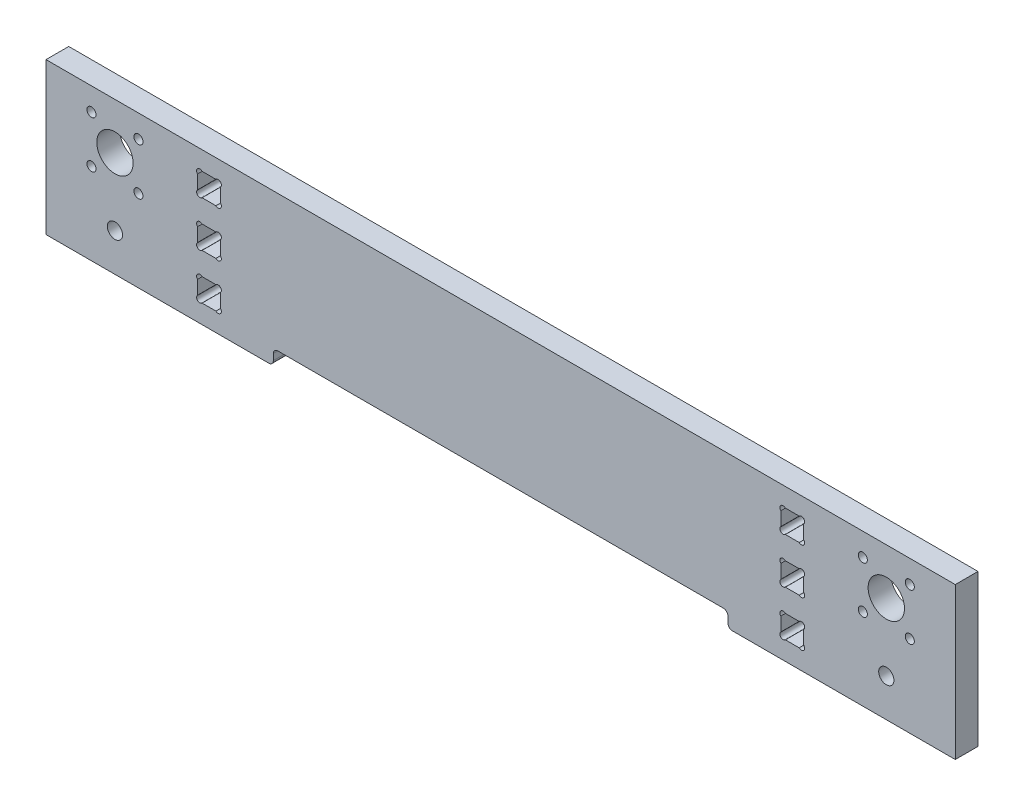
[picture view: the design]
ISO-10303-21;
HEADER;
FILE_DESCRIPTION(('STEP AP214'),'2;1');
FILE_NAME('part.step','',(''),(''),'','','');
FILE_SCHEMA(('AUTOMOTIVE_DESIGN { 1 0 10303 214 1 1 1 1 }'));
ENDSEC;
DATA;
#1=APPLICATION_CONTEXT('core data for automotive mechanical design processes');
#2=APPLICATION_PROTOCOL_DEFINITION('international standard','automotive_design',2000,#1);
#3=PRODUCT_CONTEXT('',#1,'mechanical');
#4=PRODUCT('Part','Part','',(#3));
#5=PRODUCT_RELATED_PRODUCT_CATEGORY('part','',(#4));
#6=PRODUCT_DEFINITION_FORMATION('','',#4);
#7=PRODUCT_DEFINITION_CONTEXT('part definition',#1,'design');
#8=PRODUCT_DEFINITION('design','',#6,#7);
#9=PRODUCT_DEFINITION_SHAPE('','',#8);
#10=(LENGTH_UNIT() NAMED_UNIT(*) SI_UNIT(.MILLI.,.METRE.));
#11=(NAMED_UNIT(*) PLANE_ANGLE_UNIT() SI_UNIT($,.RADIAN.));
#12=(NAMED_UNIT(*) SI_UNIT($,.STERADIAN.) SOLID_ANGLE_UNIT());
#13=UNCERTAINTY_MEASURE_WITH_UNIT(LENGTH_MEASURE(1.E-05),#10,'distance_accuracy_value','');
#14=(GEOMETRIC_REPRESENTATION_CONTEXT(3) GLOBAL_UNCERTAINTY_ASSIGNED_CONTEXT((#13)) GLOBAL_UNIT_ASSIGNED_CONTEXT((#10,
#11,#12)) REPRESENTATION_CONTEXT('',''));
#15=CARTESIAN_POINT('',(0.,0.,0.));
#16=DIRECTION('',(0.,0.,1.));
#17=DIRECTION('',(1.,0.,0.));
#18=AXIS2_PLACEMENT_3D('',#15,#16,#17);
#19=CARTESIAN_POINT('',(0.,0.,15.));
#20=DIRECTION('',(0.,0.,-1.));
#21=DIRECTION('',(-1.,0.,0.));
#22=AXIS2_PLACEMENT_3D('',#19,#20,#21);
#23=PLANE('',#22);
#24=CARTESIAN_POINT('',(45.5,25.,15.));
#25=DIRECTION('',(0.,0.,1.));
#26=DIRECTION('',(1.,0.,0.));
#27=AXIS2_PLACEMENT_3D('',#24,#25,#26);
#28=CIRCLE('',#27,5.025);
#29=CARTESIAN_POINT('',(50.5249999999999,25.,15.));
#30=VERTEX_POINT('',#29);
#31=EDGE_CURVE('E1678',#30,#30,#28,.T.);
#32=ORIENTED_EDGE('',*,*,#31,.F.);
#33=EDGE_LOOP('',(#32));
#34=FACE_BOUND('',#33,.T.);
#35=CARTESIAN_POINT('',(554.5,25.,15.));
#36=DIRECTION('',(0.,0.,1.));
#37=DIRECTION('',(1.,0.,0.));
#38=AXIS2_PLACEMENT_3D('',#35,#36,#37);
#39=CIRCLE('',#38,5.025);
#40=CARTESIAN_POINT('',(559.525,25.,15.));
#41=VERTEX_POINT('',#40);
#42=EDGE_CURVE('E1677',#41,#41,#39,.T.);
#43=ORIENTED_EDGE('',*,*,#42,.F.);
#44=EDGE_LOOP('',(#43));
#45=FACE_BOUND('',#44,.T.);
#46=CARTESIAN_POINT('',(539.,85.,15.));
#47=DIRECTION('',(0.,0.,1.));
#48=DIRECTION('',(1.,0.,0.));
#49=AXIS2_PLACEMENT_3D('',#46,#47,#48);
#50=CIRCLE('',#49,3.00000000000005);
#51=CARTESIAN_POINT('',(542.,85.,15.));
#52=VERTEX_POINT('',#51);
#53=EDGE_CURVE('E1689',#52,#52,#50,.T.);
#54=ORIENTED_EDGE('',*,*,#53,.F.);
#55=EDGE_LOOP('',(#54));
#56=FACE_BOUND('',#55,.T.);
#57=CARTESIAN_POINT('',(570.,85.,15.));
#58=DIRECTION('',(0.,0.,1.));
#59=DIRECTION('',(1.,0.,0.));
#60=AXIS2_PLACEMENT_3D('',#57,#58,#59);
#61=CIRCLE('',#60,3.00000000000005);
#62=CARTESIAN_POINT('',(573.,85.,15.));
#63=VERTEX_POINT('',#62);
#64=EDGE_CURVE('E1695',#63,#63,#61,.T.);
#65=ORIENTED_EDGE('',*,*,#64,.F.);
#66=EDGE_LOOP('',(#65));
#67=FACE_BOUND('',#66,.T.);
#68=CARTESIAN_POINT('',(570.,54.,15.));
#69=DIRECTION('',(0.,0.,1.));
#70=DIRECTION('',(1.,0.,0.));
#71=AXIS2_PLACEMENT_3D('',#68,#69,#70);
#72=CIRCLE('',#71,3.00000000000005);
#73=CARTESIAN_POINT('',(573.,54.,15.));
#74=VERTEX_POINT('',#73);
#75=EDGE_CURVE('E1703',#74,#74,#72,.T.);
#76=ORIENTED_EDGE('',*,*,#75,.F.);
#77=EDGE_LOOP('',(#76));
#78=FACE_BOUND('',#77,.T.);
#79=CARTESIAN_POINT('',(554.5,69.5,15.));
#80=DIRECTION('',(0.,0.,1.));
#81=DIRECTION('',(1.,0.,0.));
#82=AXIS2_PLACEMENT_3D('',#79,#80,#81);
#83=CIRCLE('',#82,12.);
#84=CARTESIAN_POINT('',(566.5,69.5,15.));
#85=VERTEX_POINT('',#84);
#86=EDGE_CURVE('E1711',#85,#85,#83,.T.);
#87=ORIENTED_EDGE('',*,*,#86,.F.);
#88=EDGE_LOOP('',(#87));
#89=FACE_BOUND('',#88,.T.);
#90=CARTESIAN_POINT('',(539.,54.,15.));
#91=DIRECTION('',(0.,0.,1.));
#92=DIRECTION('',(1.,0.,0.));
#93=AXIS2_PLACEMENT_3D('',#90,#91,#92);
#94=CIRCLE('',#93,3.00000000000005);
#95=CARTESIAN_POINT('',(542.,54.,15.));
#96=VERTEX_POINT('',#95);
#97=EDGE_CURVE('E423',#96,#96,#94,.T.);
#98=ORIENTED_EDGE('',*,*,#97,.F.);
#99=EDGE_LOOP('',(#98));
#100=FACE_BOUND('',#99,.T.);
#101=DIRECTION('',(-1.,0.,0.));
#102=VECTOR('',#101,1.);
#103=CARTESIAN_POINT('',(497.,27.4500000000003,15.));
#104=LINE('',#103,#102);
#105=CARTESIAN_POINT('',(497.,27.4500000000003,15.));
#106=VERTEX_POINT('',#105);
#107=CARTESIAN_POINT('',(487.9,27.4500000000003,15.));
#108=VERTEX_POINT('',#107);
#109=EDGE_CURVE('E436',#106,#108,#104,.T.);
#110=ORIENTED_EDGE('',*,*,#109,.F.);
#111=CARTESIAN_POINT('',(498.5,25.9500000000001,15.));
#112=DIRECTION('',(0.,0.,1.));
#113=DIRECTION('',(1.,0.,0.));
#114=AXIS2_PLACEMENT_3D('',#111,#112,#113);
#115=CIRCLE('',#114,2.12132034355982);
#116=CARTESIAN_POINT('',(500.,24.4499999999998,15.));
#117=VERTEX_POINT('',#116);
#118=EDGE_CURVE('E415',#117,#106,#115,.T.);
#119=ORIENTED_EDGE('',*,*,#118,.F.);
#120=DIRECTION('',(0.,1.,0.));
#121=VECTOR('',#120,1.);
#122=CARTESIAN_POINT('',(500.,15.3499999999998,15.));
#123=LINE('',#122,#121);
#124=CARTESIAN_POINT('',(500.,15.3499999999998,15.));
#125=VERTEX_POINT('',#124);
#126=EDGE_CURVE('E426',#125,#117,#123,.T.);
#127=ORIENTED_EDGE('',*,*,#126,.F.);
#128=CARTESIAN_POINT('',(498.5,13.8499999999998,15.));
#129=DIRECTION('',(0.,0.,1.));
#130=DIRECTION('',(1.,0.,0.));
#131=AXIS2_PLACEMENT_3D('',#128,#129,#130);
#132=CIRCLE('',#131,2.12132034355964);
#133=CARTESIAN_POINT('',(497.,12.3499999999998,15.));
#134=VERTEX_POINT('',#133);
#135=EDGE_CURVE('E431',#134,#125,#132,.T.);
#136=ORIENTED_EDGE('',*,*,#135,.F.);
#137=DIRECTION('',(1.,0.,0.));
#138=VECTOR('',#137,1.);
#139=CARTESIAN_POINT('',(487.9,12.3499999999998,15.));
#140=LINE('',#139,#138);
#141=CARTESIAN_POINT('',(487.9,12.3499999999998,15.));
#142=VERTEX_POINT('',#141);
#143=EDGE_CURVE('E1736',#142,#134,#140,.T.);
#144=ORIENTED_EDGE('',*,*,#143,.F.);
#145=CARTESIAN_POINT('',(486.4,13.8499999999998,15.));
#146=DIRECTION('',(0.,0.,1.));
#147=DIRECTION('',(1.,0.,0.));
#148=AXIS2_PLACEMENT_3D('',#145,#146,#147);
#149=CIRCLE('',#148,2.12132034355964);
#150=CARTESIAN_POINT('',(484.9,15.3499999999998,15.));
#151=VERTEX_POINT('',#150);
#152=EDGE_CURVE('E1739',#151,#142,#149,.T.);
#153=ORIENTED_EDGE('',*,*,#152,.F.);
#154=DIRECTION('',(0.,-1.,0.));
#155=VECTOR('',#154,1.);
#156=CARTESIAN_POINT('',(484.9,24.4499999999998,15.));
#157=LINE('',#156,#155);
#158=CARTESIAN_POINT('',(484.9,24.4499999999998,15.));
#159=VERTEX_POINT('',#158);
#160=EDGE_CURVE('E1742',#159,#151,#157,.T.);
#161=ORIENTED_EDGE('',*,*,#160,.F.);
#162=CARTESIAN_POINT('',(486.4,25.9500000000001,15.));
#163=DIRECTION('',(0.,0.,-1.));
#164=DIRECTION('',(-1.,0.,0.));
#165=AXIS2_PLACEMENT_3D('',#162,#163,#164);
#166=CIRCLE('',#165,2.12132034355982);
#167=EDGE_CURVE('E441',#159,#108,#166,.T.);
#168=ORIENTED_EDGE('',*,*,#167,.T.);
#169=EDGE_LOOP('',(#110,#119,#127,#136,#144,#153,#161,#168));
#170=FACE_BOUND('',#169,.T.);
#171=DIRECTION('',(0.,-1.,0.));
#172=VECTOR('',#171,1.);
#173=CARTESIAN_POINT('',(450.,0.,15.));
#174=LINE('',#173,#172);
#175=CARTESIAN_POINT('',(450.,6.99999999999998,15.));
#176=VERTEX_POINT('',#175);
#177=CARTESIAN_POINT('',(450.,2.99999999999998,15.));
#178=VERTEX_POINT('',#177);
#179=EDGE_CURVE('E819',#176,#178,#174,.T.);
#180=ORIENTED_EDGE('',*,*,#179,.T.);
#181=CARTESIAN_POINT('',(453.,2.99999999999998,15.));
#182=DIRECTION('',(0.,0.,-1.));
#183=DIRECTION('',(-1.,0.,0.));
#184=AXIS2_PLACEMENT_3D('',#181,#182,#183);
#185=CIRCLE('',#184,3.);
#186=CARTESIAN_POINT('',(453.,0.,15.));
#187=VERTEX_POINT('',#186);
#188=EDGE_CURVE('E873',#178,#187,#185,.F.);
#189=ORIENTED_EDGE('',*,*,#188,.T.);
#190=DIRECTION('',(1.,0.,0.));
#191=VECTOR('',#190,1.);
#192=CARTESIAN_POINT('',(600.,0.,15.));
#193=LINE('',#192,#191);
#194=CARTESIAN_POINT('',(600.,0.,15.));
#195=VERTEX_POINT('',#194);
#196=EDGE_CURVE('E822',#187,#195,#193,.T.);
#197=ORIENTED_EDGE('',*,*,#196,.T.);
#198=DIRECTION('',(0.,1.,0.));
#199=VECTOR('',#198,1.);
#200=CARTESIAN_POINT('',(600.,0.,15.));
#201=LINE('',#200,#199);
#202=CARTESIAN_POINT('',(600.,100.,15.));
#203=VERTEX_POINT('',#202);
#204=EDGE_CURVE('E824',#195,#203,#201,.T.);
#205=ORIENTED_EDGE('',*,*,#204,.T.);
#206=DIRECTION('',(-1.,0.,0.));
#207=VECTOR('',#206,1.);
#208=CARTESIAN_POINT('',(0.,100.,15.));
#209=LINE('',#208,#207);
#210=CARTESIAN_POINT('',(0.,100.,15.));
#211=VERTEX_POINT('',#210);
#212=EDGE_CURVE('E826',#203,#211,#209,.T.);
#213=ORIENTED_EDGE('',*,*,#212,.T.);
#214=DIRECTION('',(0.,-1.,0.));
#215=VECTOR('',#214,1.);
#216=CARTESIAN_POINT('',(0.,0.,15.));
#217=LINE('',#216,#215);
#218=CARTESIAN_POINT('',(0.,0.,15.));
#219=VERTEX_POINT('',#218);
#220=EDGE_CURVE('E828',#211,#219,#217,.T.);
#221=ORIENTED_EDGE('',*,*,#220,.T.);
#222=DIRECTION('',(1.,0.,0.));
#223=VECTOR('',#222,1.);
#224=CARTESIAN_POINT('',(150.,0.,15.));
#225=LINE('',#224,#223);
#226=CARTESIAN_POINT('',(147.,0.,15.));
#227=VERTEX_POINT('',#226);
#228=EDGE_CURVE('E811',#219,#227,#225,.T.);
#229=ORIENTED_EDGE('',*,*,#228,.T.);
#230=CARTESIAN_POINT('',(147.,3.00000000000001,15.));
#231=DIRECTION('',(0.,0.,-1.));
#232=DIRECTION('',(-1.,0.,0.));
#233=AXIS2_PLACEMENT_3D('',#230,#231,#232);
#234=CIRCLE('',#233,3.);
#235=CARTESIAN_POINT('',(150.,3.,15.));
#236=VERTEX_POINT('',#235);
#237=EDGE_CURVE('E871',#227,#236,#234,.F.);
#238=ORIENTED_EDGE('',*,*,#237,.T.);
#239=DIRECTION('',(0.,1.,0.));
#240=VECTOR('',#239,1.);
#241=CARTESIAN_POINT('',(150.,9.99999999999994,15.));
#242=LINE('',#241,#240);
#243=CARTESIAN_POINT('',(150.,6.99999999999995,15.));
#244=VERTEX_POINT('',#243);
#245=EDGE_CURVE('E814',#236,#244,#242,.T.);
#246=ORIENTED_EDGE('',*,*,#245,.T.);
#247=CARTESIAN_POINT('',(153.,6.99999999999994,15.));
#248=DIRECTION('',(0.,0.,-1.));
#249=DIRECTION('',(-1.,0.,0.));
#250=AXIS2_PLACEMENT_3D('',#247,#248,#249);
#251=CIRCLE('',#250,3.);
#252=CARTESIAN_POINT('',(153.,9.99999999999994,15.));
#253=VERTEX_POINT('',#252);
#254=EDGE_CURVE('E11',#244,#253,#251,.T.);
#255=ORIENTED_EDGE('',*,*,#254,.T.);
#256=DIRECTION('',(1.,0.,0.));
#257=VECTOR('',#256,1.);
#258=CARTESIAN_POINT('',(450.,9.99999999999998,15.));
#259=LINE('',#258,#257);
#260=CARTESIAN_POINT('',(447.,9.99999999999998,15.));
#261=VERTEX_POINT('',#260);
#262=EDGE_CURVE('E817',#253,#261,#259,.T.);
#263=ORIENTED_EDGE('',*,*,#262,.T.);
#264=CARTESIAN_POINT('',(447.,6.99999999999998,15.));
#265=DIRECTION('',(0.,0.,-1.));
#266=DIRECTION('',(-1.,0.,0.));
#267=AXIS2_PLACEMENT_3D('',#264,#265,#266);
#268=CIRCLE('',#267,3.);
#269=EDGE_CURVE('E888',#261,#176,#268,.T.);
#270=ORIENTED_EDGE('',*,*,#269,.T.);
#271=EDGE_LOOP('',(#180,#189,#197,#205,#213,#221,#229,#238,#246,#255,#263,#270));
#272=FACE_BOUND('',#271,.T.);
#273=CARTESIAN_POINT('',(498.5,86.1500000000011,15.));
#274=DIRECTION('',(0.,0.,1.));
#275=DIRECTION('',(1.,0.,0.));
#276=AXIS2_PLACEMENT_3D('',#273,#274,#275);
#277=CIRCLE('',#276,2.12132034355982);
#278=CARTESIAN_POINT('',(500.,84.6500000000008,15.));
#279=VERTEX_POINT('',#278);
#280=CARTESIAN_POINT('',(497.,87.6500000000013,15.));
#281=VERTEX_POINT('',#280);
#282=EDGE_CURVE('E774',#279,#281,#277,.T.);
#283=ORIENTED_EDGE('',*,*,#282,.F.);
#284=DIRECTION('',(0.,1.,0.));
#285=VECTOR('',#284,1.);
#286=CARTESIAN_POINT('',(500.,0.,15.));
#287=LINE('',#286,#285);
#288=CARTESIAN_POINT('',(500.,75.5500000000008,15.));
#289=VERTEX_POINT('',#288);
#290=EDGE_CURVE('E726',#289,#279,#287,.T.);
#291=ORIENTED_EDGE('',*,*,#290,.F.);
#292=CARTESIAN_POINT('',(498.5,74.0500000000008,15.));
#293=DIRECTION('',(0.,0.,1.));
#294=DIRECTION('',(1.,0.,0.));
#295=AXIS2_PLACEMENT_3D('',#292,#293,#294);
#296=CIRCLE('',#295,2.12132034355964);
#297=CARTESIAN_POINT('',(497.,72.5500000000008,15.));
#298=VERTEX_POINT('',#297);
#299=EDGE_CURVE('E752',#298,#289,#296,.T.);
#300=ORIENTED_EDGE('',*,*,#299,.F.);
#301=DIRECTION('',(1.,0.,0.));
#302=VECTOR('',#301,1.);
#303=CARTESIAN_POINT('',(-1.10641044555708E-13,72.5500000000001,15.));
#304=LINE('',#303,#302);
#305=CARTESIAN_POINT('',(487.9,72.5500000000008,15.));
#306=VERTEX_POINT('',#305);
#307=EDGE_CURVE('E789',#306,#298,#304,.T.);
#308=ORIENTED_EDGE('',*,*,#307,.F.);
#309=CARTESIAN_POINT('',(486.4,74.0500000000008,15.));
#310=DIRECTION('',(0.,0.,1.));
#311=DIRECTION('',(1.,0.,0.));
#312=AXIS2_PLACEMENT_3D('',#309,#310,#311);
#313=CIRCLE('',#312,2.12132034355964);
#314=CARTESIAN_POINT('',(484.9,75.5500000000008,15.));
#315=VERTEX_POINT('',#314);
#316=EDGE_CURVE('E786',#315,#306,#313,.T.);
#317=ORIENTED_EDGE('',*,*,#316,.F.);
#318=DIRECTION('',(0.,-1.,0.));
#319=VECTOR('',#318,1.);
#320=CARTESIAN_POINT('',(484.9,-2.95795134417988E-12,15.));
#321=LINE('',#320,#319);
#322=CARTESIAN_POINT('',(484.9,84.6500000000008,15.));
#323=VERTEX_POINT('',#322);
#324=EDGE_CURVE('E783',#323,#315,#321,.T.);
#325=ORIENTED_EDGE('',*,*,#324,.F.);
#326=CARTESIAN_POINT('',(486.4,86.1500000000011,15.));
#327=DIRECTION('',(0.,0.,1.));
#328=DIRECTION('',(1.,0.,0.));
#329=AXIS2_PLACEMENT_3D('',#326,#327,#328);
#330=CIRCLE('',#329,2.12132034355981);
#331=CARTESIAN_POINT('',(487.9,87.6500000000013,15.));
#332=VERTEX_POINT('',#331);
#333=EDGE_CURVE('E780',#323,#332,#330,.F.);
#334=ORIENTED_EDGE('',*,*,#333,.T.);
#335=DIRECTION('',(-1.,0.,0.));
#336=VECTOR('',#335,1.);
#337=CARTESIAN_POINT('',(0.,87.6500000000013,15.));
#338=LINE('',#337,#336);
#339=EDGE_CURVE('E777',#281,#332,#338,.T.);
#340=ORIENTED_EDGE('',*,*,#339,.F.);
#341=EDGE_LOOP('',(#283,#291,#300,#308,#317,#325,#334,#340));
#342=FACE_BOUND('',#341,.T.);
#343=CARTESIAN_POINT('',(113.6,86.1500000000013,15.));
#344=DIRECTION('',(0.,0.,1.));
#345=DIRECTION('',(1.,0.,0.));
#346=AXIS2_PLACEMENT_3D('',#343,#344,#345);
#347=CIRCLE('',#346,2.12132034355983);
#348=CARTESIAN_POINT('',(115.1,84.650000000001,15.));
#349=VERTEX_POINT('',#348);
#350=CARTESIAN_POINT('',(112.1,87.6500000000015,15.));
#351=VERTEX_POINT('',#350);
#352=EDGE_CURVE('E721',#349,#351,#347,.T.);
#353=ORIENTED_EDGE('',*,*,#352,.F.);
#354=DIRECTION('',(0.,1.,0.));
#355=VECTOR('',#354,1.);
#356=CARTESIAN_POINT('',(115.1,0.,15.));
#357=LINE('',#356,#355);
#358=CARTESIAN_POINT('',(115.1,75.550000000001,15.));
#359=VERTEX_POINT('',#358);
#360=EDGE_CURVE('E724',#359,#349,#357,.T.);
#361=ORIENTED_EDGE('',*,*,#360,.F.);
#362=CARTESIAN_POINT('',(113.6,74.050000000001,15.));
#363=DIRECTION('',(0.,0.,1.));
#364=DIRECTION('',(1.,0.,0.));
#365=AXIS2_PLACEMENT_3D('',#362,#363,#364);
#366=CIRCLE('',#365,2.12132034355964);
#367=CARTESIAN_POINT('',(112.1,72.550000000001,15.));
#368=VERTEX_POINT('',#367);
#369=EDGE_CURVE('E702',#368,#359,#366,.T.);
#370=ORIENTED_EDGE('',*,*,#369,.F.);
#371=DIRECTION('',(1.,0.,0.));
#372=VECTOR('',#371,1.);
#373=CARTESIAN_POINT('',(-1.10641044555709E-13,72.5500000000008,15.));
#374=LINE('',#373,#372);
#375=CARTESIAN_POINT('',(103.,72.550000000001,15.));
#376=VERTEX_POINT('',#375);
#377=EDGE_CURVE('E705',#376,#368,#374,.T.);
#378=ORIENTED_EDGE('',*,*,#377,.F.);
#379=CARTESIAN_POINT('',(101.5,74.050000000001,15.));
#380=DIRECTION('',(0.,0.,1.));
#381=DIRECTION('',(1.,0.,0.));
#382=AXIS2_PLACEMENT_3D('',#379,#380,#381);
#383=CIRCLE('',#382,2.12132034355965);
#384=CARTESIAN_POINT('',(100.,75.550000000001,15.));
#385=VERTEX_POINT('',#384);
#386=EDGE_CURVE('E709',#385,#376,#383,.T.);
#387=ORIENTED_EDGE('',*,*,#386,.F.);
#388=DIRECTION('',(0.,-1.,0.));
#389=VECTOR('',#388,1.);
#390=CARTESIAN_POINT('',(100.,0.,15.));
#391=LINE('',#390,#389);
#392=CARTESIAN_POINT('',(100.,84.650000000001,15.));
#393=VERTEX_POINT('',#392);
#394=EDGE_CURVE('E712',#393,#385,#391,.T.);
#395=ORIENTED_EDGE('',*,*,#394,.F.);
#396=CARTESIAN_POINT('',(101.5,86.1500000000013,15.));
#397=DIRECTION('',(0.,0.,1.));
#398=DIRECTION('',(1.,0.,0.));
#399=AXIS2_PLACEMENT_3D('',#396,#397,#398);
#400=CIRCLE('',#399,2.12132034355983);
#401=CARTESIAN_POINT('',(103.,87.6500000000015,15.));
#402=VERTEX_POINT('',#401);
#403=EDGE_CURVE('E715',#393,#402,#400,.F.);
#404=ORIENTED_EDGE('',*,*,#403,.T.);
#405=DIRECTION('',(-1.,0.,0.));
#406=VECTOR('',#405,1.);
#407=CARTESIAN_POINT('',(-1.33669022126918E-13,87.6500000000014,15.));
#408=LINE('',#407,#406);
#409=EDGE_CURVE('E718',#351,#402,#408,.T.);
#410=ORIENTED_EDGE('',*,*,#409,.F.);
#411=EDGE_LOOP('',(#353,#361,#370,#378,#387,#395,#404,#410));
#412=FACE_BOUND('',#411,.T.);
#413=CARTESIAN_POINT('',(113.6,56.0500000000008,15.));
#414=DIRECTION('',(0.,0.,1.));
#415=DIRECTION('',(1.,0.,0.));
#416=AXIS2_PLACEMENT_3D('',#413,#414,#415);
#417=CIRCLE('',#416,2.12132034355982);
#418=CARTESIAN_POINT('',(115.1,54.5500000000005,15.));
#419=VERTEX_POINT('',#418);
#420=CARTESIAN_POINT('',(112.1,57.550000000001,15.));
#421=VERTEX_POINT('',#420);
#422=EDGE_CURVE('E658',#419,#421,#417,.T.);
#423=ORIENTED_EDGE('',*,*,#422,.F.);
#424=DIRECTION('',(0.,1.,0.));
#425=VECTOR('',#424,1.);
#426=CARTESIAN_POINT('',(115.1,0.,15.));
#427=LINE('',#426,#425);
#428=CARTESIAN_POINT('',(115.1,45.4500000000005,15.));
#429=VERTEX_POINT('',#428);
#430=EDGE_CURVE('E661',#429,#419,#427,.T.);
#431=ORIENTED_EDGE('',*,*,#430,.F.);
#432=CARTESIAN_POINT('',(113.6,43.9500000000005,15.));
#433=DIRECTION('',(0.,0.,1.));
#434=DIRECTION('',(1.,0.,0.));
#435=AXIS2_PLACEMENT_3D('',#432,#433,#434);
#436=CIRCLE('',#435,2.12132034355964);
#437=CARTESIAN_POINT('',(112.1,42.4500000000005,15.));
#438=VERTEX_POINT('',#437);
#439=EDGE_CURVE('E639',#438,#429,#436,.T.);
#440=ORIENTED_EDGE('',*,*,#439,.F.);
#441=DIRECTION('',(1.,0.,0.));
#442=VECTOR('',#441,1.);
#443=CARTESIAN_POINT('',(0.,42.4500000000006,15.));
#444=LINE('',#443,#442);
#445=CARTESIAN_POINT('',(103.,42.4500000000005,15.));
#446=VERTEX_POINT('',#445);
#447=EDGE_CURVE('E642',#446,#438,#444,.T.);
#448=ORIENTED_EDGE('',*,*,#447,.F.);
#449=CARTESIAN_POINT('',(101.5,43.9500000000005,15.));
#450=DIRECTION('',(0.,0.,1.));
#451=DIRECTION('',(1.,0.,0.));
#452=AXIS2_PLACEMENT_3D('',#449,#450,#451);
#453=CIRCLE('',#452,2.12132034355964);
#454=CARTESIAN_POINT('',(100.,45.4500000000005,15.));
#455=VERTEX_POINT('',#454);
#456=EDGE_CURVE('E646',#455,#446,#453,.T.);
#457=ORIENTED_EDGE('',*,*,#456,.F.);
#458=DIRECTION('',(0.,-1.,0.));
#459=VECTOR('',#458,1.);
#460=CARTESIAN_POINT('',(100.,0.,15.));
#461=LINE('',#460,#459);
#462=CARTESIAN_POINT('',(100.,54.5500000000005,15.));
#463=VERTEX_POINT('',#462);
#464=EDGE_CURVE('E649',#463,#455,#461,.T.);
#465=ORIENTED_EDGE('',*,*,#464,.F.);
#466=CARTESIAN_POINT('',(101.5,56.0500000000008,15.));
#467=DIRECTION('',(0.,0.,1.));
#468=DIRECTION('',(1.,0.,0.));
#469=AXIS2_PLACEMENT_3D('',#466,#467,#468);
#470=CIRCLE('',#469,2.12132034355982);
#471=CARTESIAN_POINT('',(103.,57.550000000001,15.));
#472=VERTEX_POINT('',#471);
#473=EDGE_CURVE('E652',#463,#472,#470,.F.);
#474=ORIENTED_EDGE('',*,*,#473,.T.);
#475=DIRECTION('',(-1.,0.,0.));
#476=VECTOR('',#475,1.);
#477=CARTESIAN_POINT('',(0.,57.5500000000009,15.));
#478=LINE('',#477,#476);
#479=EDGE_CURVE('E655',#421,#472,#478,.T.);
#480=ORIENTED_EDGE('',*,*,#479,.F.);
#481=EDGE_LOOP('',(#423,#431,#440,#448,#457,#465,#474,#480));
#482=FACE_BOUND('',#481,.T.);
#483=CARTESIAN_POINT('',(113.6,25.9500000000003,15.));
#484=DIRECTION('',(0.,0.,1.));
#485=DIRECTION('',(1.,0.,0.));
#486=AXIS2_PLACEMENT_3D('',#483,#484,#485);
#487=CIRCLE('',#486,2.12132034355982);
#488=CARTESIAN_POINT('',(115.1,24.45,15.));
#489=VERTEX_POINT('',#488);
#490=CARTESIAN_POINT('',(112.1,27.4500000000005,15.));
#491=VERTEX_POINT('',#490);
#492=EDGE_CURVE('E595',#489,#491,#487,.T.);
#493=ORIENTED_EDGE('',*,*,#492,.F.);
#494=DIRECTION('',(0.,1.,0.));
#495=VECTOR('',#494,1.);
#496=CARTESIAN_POINT('',(115.1,0.,15.));
#497=LINE('',#496,#495);
#498=CARTESIAN_POINT('',(115.1,15.35,15.));
#499=VERTEX_POINT('',#498);
#500=EDGE_CURVE('E598',#499,#489,#497,.T.);
#501=ORIENTED_EDGE('',*,*,#500,.F.);
#502=CARTESIAN_POINT('',(113.6,13.85,15.));
#503=DIRECTION('',(0.,0.,1.));
#504=DIRECTION('',(1.,0.,0.));
#505=AXIS2_PLACEMENT_3D('',#502,#503,#504);
#506=CIRCLE('',#505,2.12132034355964);
#507=CARTESIAN_POINT('',(112.1,12.35,15.));
#508=VERTEX_POINT('',#507);
#509=EDGE_CURVE('E576',#508,#499,#506,.T.);
#510=ORIENTED_EDGE('',*,*,#509,.F.);
#511=DIRECTION('',(1.,0.,0.));
#512=VECTOR('',#511,1.);
#513=CARTESIAN_POINT('',(0.,12.35,15.));
#514=LINE('',#513,#512);
#515=CARTESIAN_POINT('',(103.,12.35,15.));
#516=VERTEX_POINT('',#515);
#517=EDGE_CURVE('E579',#516,#508,#514,.T.);
#518=ORIENTED_EDGE('',*,*,#517,.F.);
#519=CARTESIAN_POINT('',(101.5,13.85,15.));
#520=DIRECTION('',(0.,0.,1.));
#521=DIRECTION('',(1.,0.,0.));
#522=AXIS2_PLACEMENT_3D('',#519,#520,#521);
#523=CIRCLE('',#522,2.12132034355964);
#524=CARTESIAN_POINT('',(100.,15.35,15.));
#525=VERTEX_POINT('',#524);
#526=EDGE_CURVE('E583',#525,#516,#523,.T.);
#527=ORIENTED_EDGE('',*,*,#526,.F.);
#528=DIRECTION('',(0.,-1.,0.));
#529=VECTOR('',#528,1.);
#530=CARTESIAN_POINT('',(100.,0.,15.));
#531=LINE('',#530,#529);
#532=CARTESIAN_POINT('',(100.,24.45,15.));
#533=VERTEX_POINT('',#532);
#534=EDGE_CURVE('E586',#533,#525,#531,.T.);
#535=ORIENTED_EDGE('',*,*,#534,.F.);
#536=CARTESIAN_POINT('',(101.5,25.9500000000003,15.));
#537=DIRECTION('',(0.,0.,1.));
#538=DIRECTION('',(1.,0.,0.));
#539=AXIS2_PLACEMENT_3D('',#536,#537,#538);
#540=CIRCLE('',#539,2.12132034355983);
#541=CARTESIAN_POINT('',(103.,27.4500000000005,15.));
#542=VERTEX_POINT('',#541);
#543=EDGE_CURVE('E589',#533,#542,#540,.F.);
#544=ORIENTED_EDGE('',*,*,#543,.T.);
#545=DIRECTION('',(-1.,0.,0.));
#546=VECTOR('',#545,1.);
#547=CARTESIAN_POINT('',(0.,27.4500000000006,15.));
#548=LINE('',#547,#546);
#549=EDGE_CURVE('E592',#491,#542,#548,.T.);
#550=ORIENTED_EDGE('',*,*,#549,.F.);
#551=EDGE_LOOP('',(#493,#501,#510,#518,#527,#535,#544,#550));
#552=FACE_BOUND('',#551,.T.);
#553=CARTESIAN_POINT('',(45.5,69.5,15.));
#554=DIRECTION('',(0.,0.,1.));
#555=DIRECTION('',(1.,0.,0.));
#556=AXIS2_PLACEMENT_3D('',#553,#554,#555);
#557=CIRCLE('',#556,12.);
#558=CARTESIAN_POINT('',(57.4999999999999,69.5,15.));
#559=VERTEX_POINT('',#558);
#560=EDGE_CURVE('E553',#559,#559,#557,.T.);
#561=ORIENTED_EDGE('',*,*,#560,.F.);
#562=EDGE_LOOP('',(#561));
#563=FACE_BOUND('',#562,.T.);
#564=CARTESIAN_POINT('',(30.,54.,15.));
#565=DIRECTION('',(0.,0.,1.));
#566=DIRECTION('',(1.,0.,0.));
#567=AXIS2_PLACEMENT_3D('',#564,#565,#566);
#568=CIRCLE('',#567,3.);
#569=CARTESIAN_POINT('',(33.,54.,15.));
#570=VERTEX_POINT('',#569);
#571=EDGE_CURVE('E547',#570,#570,#568,.T.);
#572=ORIENTED_EDGE('',*,*,#571,.F.);
#573=EDGE_LOOP('',(#572));
#574=FACE_BOUND('',#573,.T.);
#575=CARTESIAN_POINT('',(30.,85.,15.));
#576=DIRECTION('',(0.,0.,1.));
#577=DIRECTION('',(1.,0.,0.));
#578=AXIS2_PLACEMENT_3D('',#575,#576,#577);
#579=CIRCLE('',#578,3.);
#580=CARTESIAN_POINT('',(33.,85.,15.));
#581=VERTEX_POINT('',#580);
#582=EDGE_CURVE('E541',#581,#581,#579,.T.);
#583=ORIENTED_EDGE('',*,*,#582,.F.);
#584=EDGE_LOOP('',(#583));
#585=FACE_BOUND('',#584,.T.);
#586=CARTESIAN_POINT('',(61.,85.,15.));
#587=DIRECTION('',(0.,0.,1.));
#588=DIRECTION('',(1.,0.,0.));
#589=AXIS2_PLACEMENT_3D('',#586,#587,#588);
#590=CIRCLE('',#589,3.00000000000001);
#591=CARTESIAN_POINT('',(64.,85.,15.));
#592=VERTEX_POINT('',#591);
#593=EDGE_CURVE('E535',#592,#592,#590,.T.);
#594=ORIENTED_EDGE('',*,*,#593,.F.);
#595=EDGE_LOOP('',(#594));
#596=FACE_BOUND('',#595,.T.);
#597=CARTESIAN_POINT('',(61.,54.,15.));
#598=DIRECTION('',(0.,0.,1.));
#599=DIRECTION('',(1.,0.,0.));
#600=AXIS2_PLACEMENT_3D('',#597,#598,#599);
#601=CIRCLE('',#600,3.00000000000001);
#602=CARTESIAN_POINT('',(64.,54.,15.));
#603=VERTEX_POINT('',#602);
#604=EDGE_CURVE('E529',#603,#603,#601,.T.);
#605=ORIENTED_EDGE('',*,*,#604,.F.);
#606=EDGE_LOOP('',(#605));
#607=FACE_BOUND('',#606,.T.);
#608=CARTESIAN_POINT('',(486.4,56.0500000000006,15.));
#609=DIRECTION('',(0.,0.,-1.));
#610=DIRECTION('',(-1.,0.,0.));
#611=AXIS2_PLACEMENT_3D('',#608,#609,#610);
#612=CIRCLE('',#611,2.12132034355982);
#613=CARTESIAN_POINT('',(484.9,54.5500000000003,15.));
#614=VERTEX_POINT('',#613);
#615=CARTESIAN_POINT('',(487.9,57.5500000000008,15.));
#616=VERTEX_POINT('',#615);
#617=EDGE_CURVE('E504',#614,#616,#612,.T.);
#618=ORIENTED_EDGE('',*,*,#617,.T.);
#619=DIRECTION('',(-1.,0.,0.));
#620=VECTOR('',#619,1.);
#621=CARTESIAN_POINT('',(497.,57.5500000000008,15.));
#622=LINE('',#621,#620);
#623=CARTESIAN_POINT('',(497.,57.5500000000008,15.));
#624=VERTEX_POINT('',#623);
#625=EDGE_CURVE('E501',#624,#616,#622,.T.);
#626=ORIENTED_EDGE('',*,*,#625,.F.);
#627=CARTESIAN_POINT('',(498.5,56.0500000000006,15.));
#628=DIRECTION('',(0.,0.,1.));
#629=DIRECTION('',(1.,0.,0.));
#630=AXIS2_PLACEMENT_3D('',#627,#628,#629);
#631=CIRCLE('',#630,2.12132034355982);
#632=CARTESIAN_POINT('',(500.,54.5500000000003,15.));
#633=VERTEX_POINT('',#632);
#634=EDGE_CURVE('E498',#633,#624,#631,.T.);
#635=ORIENTED_EDGE('',*,*,#634,.F.);
#636=DIRECTION('',(0.,1.,0.));
#637=VECTOR('',#636,1.);
#638=CARTESIAN_POINT('',(500.,45.4500000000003,15.));
#639=LINE('',#638,#637);
#640=CARTESIAN_POINT('',(500.,45.4500000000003,15.));
#641=VERTEX_POINT('',#640);
#642=EDGE_CURVE('E495',#641,#633,#639,.T.);
#643=ORIENTED_EDGE('',*,*,#642,.F.);
#644=CARTESIAN_POINT('',(498.5,43.9500000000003,15.));
#645=DIRECTION('',(0.,0.,1.));
#646=DIRECTION('',(1.,0.,0.));
#647=AXIS2_PLACEMENT_3D('',#644,#645,#646);
#648=CIRCLE('',#647,2.12132034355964);
#649=CARTESIAN_POINT('',(497.,42.4500000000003,15.));
#650=VERTEX_POINT('',#649);
#651=EDGE_CURVE('E492',#650,#641,#648,.T.);
#652=ORIENTED_EDGE('',*,*,#651,.F.);
#653=DIRECTION('',(1.,0.,0.));
#654=VECTOR('',#653,1.);
#655=CARTESIAN_POINT('',(487.9,42.4500000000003,15.));
#656=LINE('',#655,#654);
#657=CARTESIAN_POINT('',(487.9,42.4500000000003,15.));
#658=VERTEX_POINT('',#657);
#659=EDGE_CURVE('E489',#658,#650,#656,.T.);
#660=ORIENTED_EDGE('',*,*,#659,.F.);
#661=CARTESIAN_POINT('',(486.4,43.9500000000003,15.));
#662=DIRECTION('',(0.,0.,1.));
#663=DIRECTION('',(1.,0.,0.));
#664=AXIS2_PLACEMENT_3D('',#661,#662,#663);
#665=CIRCLE('',#664,2.12132034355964);
#666=CARTESIAN_POINT('',(484.9,45.4500000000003,15.));
#667=VERTEX_POINT('',#666);
#668=EDGE_CURVE('E485',#667,#658,#665,.T.);
#669=ORIENTED_EDGE('',*,*,#668,.F.);
#670=DIRECTION('',(0.,-1.,0.));
#671=VECTOR('',#670,1.);
#672=CARTESIAN_POINT('',(484.9,54.5500000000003,15.));
#673=LINE('',#672,#671);
#674=EDGE_CURVE('E482',#614,#667,#673,.T.);
#675=ORIENTED_EDGE('',*,*,#674,.F.);
#676=EDGE_LOOP('',(#618,#626,#635,#643,#652,#660,#669,#675));
#677=FACE_BOUND('',#676,.T.);
#678=ADVANCED_FACE('F35',(#34,#45,#56,#67,#78,#89,#100,#170,#272,#342,#412,#482,#552,#563,#574,
#585,#596,#607,#677),#23,.F.);
#679=CARTESIAN_POINT('',(0.,0.,0.));
#680=DIRECTION('',(0.,0.,-1.));
#681=DIRECTION('',(-1.,0.,0.));
#682=AXIS2_PLACEMENT_3D('',#679,#680,#681);
#683=PLANE('',#682);
#684=CARTESIAN_POINT('',(539.,85.,0.));
#685=DIRECTION('',(0.,0.,1.));
#686=DIRECTION('',(1.,0.,0.));
#687=AXIS2_PLACEMENT_3D('',#684,#685,#686);
#688=CIRCLE('',#687,3.00000000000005);
#689=CARTESIAN_POINT('',(542.,85.,0.));
#690=VERTEX_POINT('',#689);
#691=EDGE_CURVE('E1687',#690,#690,#688,.T.);
#692=ORIENTED_EDGE('',*,*,#691,.T.);
#693=EDGE_LOOP('',(#692));
#694=FACE_BOUND('',#693,.T.);
#695=CARTESIAN_POINT('',(570.,85.,0.));
#696=DIRECTION('',(0.,0.,1.));
#697=DIRECTION('',(1.,0.,0.));
#698=AXIS2_PLACEMENT_3D('',#695,#696,#697);
#699=CIRCLE('',#698,3.00000000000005);
#700=CARTESIAN_POINT('',(573.,85.,0.));
#701=VERTEX_POINT('',#700);
#702=EDGE_CURVE('E1692',#701,#701,#699,.T.);
#703=ORIENTED_EDGE('',*,*,#702,.T.);
#704=EDGE_LOOP('',(#703));
#705=FACE_BOUND('',#704,.T.);
#706=CARTESIAN_POINT('',(570.,54.,0.));
#707=DIRECTION('',(0.,0.,1.));
#708=DIRECTION('',(1.,0.,0.));
#709=AXIS2_PLACEMENT_3D('',#706,#707,#708);
#710=CIRCLE('',#709,3.00000000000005);
#711=CARTESIAN_POINT('',(573.,54.,0.));
#712=VERTEX_POINT('',#711);
#713=EDGE_CURVE('E1699',#712,#712,#710,.T.);
#714=ORIENTED_EDGE('',*,*,#713,.T.);
#715=EDGE_LOOP('',(#714));
#716=FACE_BOUND('',#715,.T.);
#717=CARTESIAN_POINT('',(554.5,69.5,0.));
#718=DIRECTION('',(0.,0.,1.));
#719=DIRECTION('',(1.,0.,0.));
#720=AXIS2_PLACEMENT_3D('',#717,#718,#719);
#721=CIRCLE('',#720,12.);
#722=CARTESIAN_POINT('',(566.5,69.5,0.));
#723=VERTEX_POINT('',#722);
#724=EDGE_CURVE('E1707',#723,#723,#721,.T.);
#725=ORIENTED_EDGE('',*,*,#724,.T.);
#726=EDGE_LOOP('',(#725));
#727=FACE_BOUND('',#726,.T.);
#728=CARTESIAN_POINT('',(539.,54.,0.));
#729=DIRECTION('',(0.,0.,1.));
#730=DIRECTION('',(1.,0.,0.));
#731=AXIS2_PLACEMENT_3D('',#728,#729,#730);
#732=CIRCLE('',#731,3.00000000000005);
#733=CARTESIAN_POINT('',(542.,54.,0.));
#734=VERTEX_POINT('',#733);
#735=EDGE_CURVE('E1715',#734,#734,#732,.T.);
#736=ORIENTED_EDGE('',*,*,#735,.T.);
#737=EDGE_LOOP('',(#736));
#738=FACE_BOUND('',#737,.T.);
#739=CARTESIAN_POINT('',(498.5,25.9500000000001,0.));
#740=DIRECTION('',(0.,0.,1.));
#741=DIRECTION('',(1.,0.,0.));
#742=AXIS2_PLACEMENT_3D('',#739,#740,#741);
#743=CIRCLE('',#742,2.12132034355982);
#744=CARTESIAN_POINT('',(500.,24.4499999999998,0.));
#745=VERTEX_POINT('',#744);
#746=CARTESIAN_POINT('',(497.,27.4500000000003,0.));
#747=VERTEX_POINT('',#746);
#748=EDGE_CURVE('E418',#745,#747,#743,.T.);
#749=ORIENTED_EDGE('',*,*,#748,.T.);
#750=DIRECTION('',(-1.,0.,0.));
#751=VECTOR('',#750,1.);
#752=CARTESIAN_POINT('',(497.,27.4500000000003,0.));
#753=LINE('',#752,#751);
#754=CARTESIAN_POINT('',(487.9,27.4500000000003,0.));
#755=VERTEX_POINT('',#754);
#756=EDGE_CURVE('E463',#747,#755,#753,.T.);
#757=ORIENTED_EDGE('',*,*,#756,.T.);
#758=CARTESIAN_POINT('',(486.4,25.9500000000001,0.));
#759=DIRECTION('',(0.,0.,-1.));
#760=DIRECTION('',(-1.,0.,0.));
#761=AXIS2_PLACEMENT_3D('',#758,#759,#760);
#762=CIRCLE('',#761,2.12132034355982);
#763=CARTESIAN_POINT('',(484.9,24.4499999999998,0.));
#764=VERTEX_POINT('',#763);
#765=EDGE_CURVE('E460',#764,#755,#762,.T.);
#766=ORIENTED_EDGE('',*,*,#765,.F.);
#767=DIRECTION('',(0.,-1.,0.));
#768=VECTOR('',#767,1.);
#769=CARTESIAN_POINT('',(484.9,24.4499999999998,0.));
#770=LINE('',#769,#768);
#771=CARTESIAN_POINT('',(484.9,15.3499999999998,0.));
#772=VERTEX_POINT('',#771);
#773=EDGE_CURVE('E457',#764,#772,#770,.T.);
#774=ORIENTED_EDGE('',*,*,#773,.T.);
#775=CARTESIAN_POINT('',(486.4,13.8499999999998,0.));
#776=DIRECTION('',(0.,0.,1.));
#777=DIRECTION('',(1.,0.,0.));
#778=AXIS2_PLACEMENT_3D('',#775,#776,#777);
#779=CIRCLE('',#778,2.12132034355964);
#780=CARTESIAN_POINT('',(487.9,12.3499999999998,0.));
#781=VERTEX_POINT('',#780);
#782=EDGE_CURVE('E454',#772,#781,#779,.T.);
#783=ORIENTED_EDGE('',*,*,#782,.T.);
#784=DIRECTION('',(1.,0.,0.));
#785=VECTOR('',#784,1.);
#786=CARTESIAN_POINT('',(487.9,12.3499999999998,0.));
#787=LINE('',#786,#785);
#788=CARTESIAN_POINT('',(497.,12.3499999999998,0.));
#789=VERTEX_POINT('',#788);
#790=EDGE_CURVE('E451',#781,#789,#787,.T.);
#791=ORIENTED_EDGE('',*,*,#790,.T.);
#792=CARTESIAN_POINT('',(498.5,13.8499999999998,0.));
#793=DIRECTION('',(0.,0.,1.));
#794=DIRECTION('',(1.,0.,0.));
#795=AXIS2_PLACEMENT_3D('',#792,#793,#794);
#796=CIRCLE('',#795,2.12132034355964);
#797=CARTESIAN_POINT('',(500.,15.3499999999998,0.));
#798=VERTEX_POINT('',#797);
#799=EDGE_CURVE('E447',#789,#798,#796,.T.);
#800=ORIENTED_EDGE('',*,*,#799,.T.);
#801=DIRECTION('',(0.,1.,0.));
#802=VECTOR('',#801,1.);
#803=CARTESIAN_POINT('',(500.,15.3499999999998,0.));
#804=LINE('',#803,#802);
#805=EDGE_CURVE('E445',#798,#745,#804,.T.);
#806=ORIENTED_EDGE('',*,*,#805,.T.);
#807=EDGE_LOOP('',(#749,#757,#766,#774,#783,#791,#800,#806));
#808=FACE_BOUND('',#807,.T.);
#809=DIRECTION('',(1.,0.,0.));
#810=VECTOR('',#809,1.);
#811=CARTESIAN_POINT('',(600.,0.,0.));
#812=LINE('',#811,#810);
#813=CARTESIAN_POINT('',(453.,0.,0.));
#814=VERTEX_POINT('',#813);
#815=CARTESIAN_POINT('',(600.,0.,0.));
#816=VERTEX_POINT('',#815);
#817=EDGE_CURVE('E841',#814,#816,#812,.T.);
#818=ORIENTED_EDGE('',*,*,#817,.F.);
#819=CARTESIAN_POINT('',(453.,2.99999999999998,0.));
#820=DIRECTION('',(0.,0.,-1.));
#821=DIRECTION('',(-1.,0.,0.));
#822=AXIS2_PLACEMENT_3D('',#819,#820,#821);
#823=CIRCLE('',#822,3.);
#824=CARTESIAN_POINT('',(450.,2.99999999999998,0.));
#825=VERTEX_POINT('',#824);
#826=EDGE_CURVE('E864',#814,#825,#823,.T.);
#827=ORIENTED_EDGE('',*,*,#826,.T.);
#828=DIRECTION('',(0.,-1.,0.));
#829=VECTOR('',#828,1.);
#830=CARTESIAN_POINT('',(450.,0.,0.));
#831=LINE('',#830,#829);
#832=CARTESIAN_POINT('',(450.,6.99999999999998,0.));
#833=VERTEX_POINT('',#832);
#834=EDGE_CURVE('E838',#833,#825,#831,.T.);
#835=ORIENTED_EDGE('',*,*,#834,.F.);
#836=CARTESIAN_POINT('',(447.,6.99999999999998,0.));
#837=DIRECTION('',(0.,0.,-1.));
#838=DIRECTION('',(-1.,0.,0.));
#839=AXIS2_PLACEMENT_3D('',#836,#837,#838);
#840=CIRCLE('',#839,3.);
#841=CARTESIAN_POINT('',(447.,9.99999999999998,0.));
#842=VERTEX_POINT('',#841);
#843=EDGE_CURVE('E886',#833,#842,#840,.F.);
#844=ORIENTED_EDGE('',*,*,#843,.T.);
#845=DIRECTION('',(1.,0.,0.));
#846=VECTOR('',#845,1.);
#847=CARTESIAN_POINT('',(450.,9.99999999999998,0.));
#848=LINE('',#847,#846);
#849=CARTESIAN_POINT('',(153.,9.99999999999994,0.));
#850=VERTEX_POINT('',#849);
#851=EDGE_CURVE('E836',#850,#842,#848,.T.);
#852=ORIENTED_EDGE('',*,*,#851,.F.);
#853=CARTESIAN_POINT('',(153.,6.99999999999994,0.));
#854=DIRECTION('',(0.,0.,-1.));
#855=DIRECTION('',(-1.,0.,0.));
#856=AXIS2_PLACEMENT_3D('',#853,#854,#855);
#857=CIRCLE('',#856,3.);
#858=CARTESIAN_POINT('',(150.,6.99999999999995,0.));
#859=VERTEX_POINT('',#858);
#860=EDGE_CURVE('E43',#850,#859,#857,.F.);
#861=ORIENTED_EDGE('',*,*,#860,.T.);
#862=DIRECTION('',(0.,1.,0.));
#863=VECTOR('',#862,1.);
#864=CARTESIAN_POINT('',(150.,9.99999999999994,0.));
#865=LINE('',#864,#863);
#866=CARTESIAN_POINT('',(150.,3.,0.));
#867=VERTEX_POINT('',#866);
#868=EDGE_CURVE('E833',#867,#859,#865,.T.);
#869=ORIENTED_EDGE('',*,*,#868,.F.);
#870=CARTESIAN_POINT('',(147.,3.00000000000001,0.));
#871=DIRECTION('',(0.,0.,-1.));
#872=DIRECTION('',(-1.,0.,0.));
#873=AXIS2_PLACEMENT_3D('',#870,#871,#872);
#874=CIRCLE('',#873,3.);
#875=CARTESIAN_POINT('',(147.,0.,0.));
#876=VERTEX_POINT('',#875);
#877=EDGE_CURVE('E862',#867,#876,#874,.T.);
#878=ORIENTED_EDGE('',*,*,#877,.T.);
#879=DIRECTION('',(1.,0.,0.));
#880=VECTOR('',#879,1.);
#881=CARTESIAN_POINT('',(150.,0.,0.));
#882=LINE('',#881,#880);
#883=CARTESIAN_POINT('',(0.,0.,0.));
#884=VERTEX_POINT('',#883);
#885=EDGE_CURVE('E796',#884,#876,#882,.T.);
#886=ORIENTED_EDGE('',*,*,#885,.F.);
#887=DIRECTION('',(0.,-1.,0.));
#888=VECTOR('',#887,1.);
#889=CARTESIAN_POINT('',(0.,0.,0.));
#890=LINE('',#889,#888);
#891=CARTESIAN_POINT('',(0.,100.,0.));
#892=VERTEX_POINT('',#891);
#893=EDGE_CURVE('E815',#892,#884,#890,.T.);
#894=ORIENTED_EDGE('',*,*,#893,.F.);
#895=DIRECTION('',(-1.,0.,0.));
#896=VECTOR('',#895,1.);
#897=CARTESIAN_POINT('',(0.,100.,0.));
#898=LINE('',#897,#896);
#899=CARTESIAN_POINT('',(600.,100.,0.));
#900=VERTEX_POINT('',#899);
#901=EDGE_CURVE('E845',#900,#892,#898,.T.);
#902=ORIENTED_EDGE('',*,*,#901,.F.);
#903=DIRECTION('',(0.,1.,0.));
#904=VECTOR('',#903,1.);
#905=CARTESIAN_POINT('',(600.,0.,0.));
#906=LINE('',#905,#904);
#907=EDGE_CURVE('E843',#816,#900,#906,.T.);
#908=ORIENTED_EDGE('',*,*,#907,.F.);
#909=EDGE_LOOP('',(#818,#827,#835,#844,#852,#861,#869,#878,#886,#894,#902,#908));
#910=FACE_BOUND('',#909,.T.);
#911=DIRECTION('',(0.,1.,0.));
#912=VECTOR('',#911,1.);
#913=CARTESIAN_POINT('',(500.,0.,0.));
#914=LINE('',#913,#912);
#915=CARTESIAN_POINT('',(500.,75.5500000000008,0.));
#916=VERTEX_POINT('',#915);
#917=CARTESIAN_POINT('',(500.,84.6500000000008,0.));
#918=VERTEX_POINT('',#917);
#919=EDGE_CURVE('E748',#916,#918,#914,.T.);
#920=ORIENTED_EDGE('',*,*,#919,.T.);
#921=CARTESIAN_POINT('',(498.5,86.1500000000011,0.));
#922=DIRECTION('',(0.,0.,1.));
#923=DIRECTION('',(1.,0.,0.));
#924=AXIS2_PLACEMENT_3D('',#921,#922,#923);
#925=CIRCLE('',#924,2.12132034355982);
#926=CARTESIAN_POINT('',(497.,87.6500000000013,0.));
#927=VERTEX_POINT('',#926);
#928=EDGE_CURVE('E751',#918,#927,#925,.T.);
#929=ORIENTED_EDGE('',*,*,#928,.T.);
#930=DIRECTION('',(-1.,0.,0.));
#931=VECTOR('',#930,1.);
#932=CARTESIAN_POINT('',(0.,87.6500000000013,0.));
#933=LINE('',#932,#931);
#934=CARTESIAN_POINT('',(487.9,87.6500000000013,0.));
#935=VERTEX_POINT('',#934);
#936=EDGE_CURVE('E755',#927,#935,#933,.T.);
#937=ORIENTED_EDGE('',*,*,#936,.T.);
#938=CARTESIAN_POINT('',(486.4,86.1500000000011,0.));
#939=DIRECTION('',(0.,0.,1.));
#940=DIRECTION('',(1.,0.,0.));
#941=AXIS2_PLACEMENT_3D('',#938,#939,#940);
#942=CIRCLE('',#941,2.12132034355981);
#943=CARTESIAN_POINT('',(484.9,84.6500000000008,0.));
#944=VERTEX_POINT('',#943);
#945=EDGE_CURVE('E758',#944,#935,#942,.F.);
#946=ORIENTED_EDGE('',*,*,#945,.F.);
#947=DIRECTION('',(0.,-1.,0.));
#948=VECTOR('',#947,1.);
#949=CARTESIAN_POINT('',(484.9,-2.95795134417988E-12,0.));
#950=LINE('',#949,#948);
#951=CARTESIAN_POINT('',(484.9,75.5500000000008,0.));
#952=VERTEX_POINT('',#951);
#953=EDGE_CURVE('E760',#944,#952,#950,.T.);
#954=ORIENTED_EDGE('',*,*,#953,.T.);
#955=CARTESIAN_POINT('',(486.4,74.0500000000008,0.));
#956=DIRECTION('',(0.,0.,1.));
#957=DIRECTION('',(1.,0.,0.));
#958=AXIS2_PLACEMENT_3D('',#955,#956,#957);
#959=CIRCLE('',#958,2.12132034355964);
#960=CARTESIAN_POINT('',(487.9,72.5500000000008,0.));
#961=VERTEX_POINT('',#960);
#962=EDGE_CURVE('E763',#952,#961,#959,.T.);
#963=ORIENTED_EDGE('',*,*,#962,.T.);
#964=DIRECTION('',(1.,0.,0.));
#965=VECTOR('',#964,1.);
#966=CARTESIAN_POINT('',(-1.10641044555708E-13,72.5500000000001,0.));
#967=LINE('',#966,#965);
#968=CARTESIAN_POINT('',(497.,72.5500000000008,0.));
#969=VERTEX_POINT('',#968);
#970=EDGE_CURVE('E766',#961,#969,#967,.T.);
#971=ORIENTED_EDGE('',*,*,#970,.T.);
#972=CARTESIAN_POINT('',(498.5,74.0500000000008,0.));
#973=DIRECTION('',(0.,0.,1.));
#974=DIRECTION('',(1.,0.,0.));
#975=AXIS2_PLACEMENT_3D('',#972,#973,#974);
#976=CIRCLE('',#975,2.12132034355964);
#977=EDGE_CURVE('E769',#969,#916,#976,.T.);
#978=ORIENTED_EDGE('',*,*,#977,.T.);
#979=EDGE_LOOP('',(#920,#929,#937,#946,#954,#963,#971,#978));
#980=FACE_BOUND('',#979,.T.);
#981=DIRECTION('',(0.,1.,0.));
#982=VECTOR('',#981,1.);
#983=CARTESIAN_POINT('',(115.1,0.,0.));
#984=LINE('',#983,#982);
#985=CARTESIAN_POINT('',(115.1,75.550000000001,0.));
#986=VERTEX_POINT('',#985);
#987=CARTESIAN_POINT('',(115.1,84.650000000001,0.));
#988=VERTEX_POINT('',#987);
#989=EDGE_CURVE('E706',#986,#988,#984,.T.);
#990=ORIENTED_EDGE('',*,*,#989,.T.);
#991=CARTESIAN_POINT('',(113.6,86.1500000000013,0.));
#992=DIRECTION('',(0.,0.,1.));
#993=DIRECTION('',(1.,0.,0.));
#994=AXIS2_PLACEMENT_3D('',#991,#992,#993);
#995=CIRCLE('',#994,2.12132034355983);
#996=CARTESIAN_POINT('',(112.1,87.6500000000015,0.));
#997=VERTEX_POINT('',#996);
#998=EDGE_CURVE('E743',#988,#997,#995,.T.);
#999=ORIENTED_EDGE('',*,*,#998,.T.);
#1000=DIRECTION('',(-1.,0.,0.));
#1001=VECTOR('',#1000,1.);
#1002=CARTESIAN_POINT('',(-1.33669022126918E-13,87.6500000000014,0.));
#1003=LINE('',#1002,#1001);
#1004=CARTESIAN_POINT('',(103.,87.6500000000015,0.));
#1005=VERTEX_POINT('',#1004);
#1006=EDGE_CURVE('E740',#997,#1005,#1003,.T.);
#1007=ORIENTED_EDGE('',*,*,#1006,.T.);
#1008=CARTESIAN_POINT('',(101.5,86.1500000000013,0.));
#1009=DIRECTION('',(0.,0.,1.));
#1010=DIRECTION('',(1.,0.,0.));
#1011=AXIS2_PLACEMENT_3D('',#1008,#1009,#1010);
#1012=CIRCLE('',#1011,2.12132034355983);
#1013=CARTESIAN_POINT('',(100.,84.650000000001,0.));
#1014=VERTEX_POINT('',#1013);
#1015=EDGE_CURVE('E738',#1014,#1005,#1012,.F.);
#1016=ORIENTED_EDGE('',*,*,#1015,.F.);
#1017=DIRECTION('',(0.,-1.,0.));
#1018=VECTOR('',#1017,1.);
#1019=CARTESIAN_POINT('',(100.,0.,0.));
#1020=LINE('',#1019,#1018);
#1021=CARTESIAN_POINT('',(100.,75.550000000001,0.));
#1022=VERTEX_POINT('',#1021);
#1023=EDGE_CURVE('E735',#1014,#1022,#1020,.T.);
#1024=ORIENTED_EDGE('',*,*,#1023,.T.);
#1025=CARTESIAN_POINT('',(101.5,74.050000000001,0.));
#1026=DIRECTION('',(0.,0.,1.));
#1027=DIRECTION('',(1.,0.,0.));
#1028=AXIS2_PLACEMENT_3D('',#1025,#1026,#1027);
#1029=CIRCLE('',#1028,2.12132034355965);
#1030=CARTESIAN_POINT('',(103.,72.550000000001,0.));
#1031=VERTEX_POINT('',#1030);
#1032=EDGE_CURVE('E732',#1022,#1031,#1029,.T.);
#1033=ORIENTED_EDGE('',*,*,#1032,.T.);
#1034=DIRECTION('',(1.,0.,0.));
#1035=VECTOR('',#1034,1.);
#1036=CARTESIAN_POINT('',(-1.10641044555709E-13,72.5500000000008,0.));
#1037=LINE('',#1036,#1035);
#1038=CARTESIAN_POINT('',(112.1,72.550000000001,0.));
#1039=VERTEX_POINT('',#1038);
#1040=EDGE_CURVE('E729',#1031,#1039,#1037,.T.);
#1041=ORIENTED_EDGE('',*,*,#1040,.T.);
#1042=CARTESIAN_POINT('',(113.6,74.050000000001,0.));
#1043=DIRECTION('',(0.,0.,1.));
#1044=DIRECTION('',(1.,0.,0.));
#1045=AXIS2_PLACEMENT_3D('',#1042,#1043,#1044);
#1046=CIRCLE('',#1045,2.12132034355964);
#1047=EDGE_CURVE('E688',#1039,#986,#1046,.T.);
#1048=ORIENTED_EDGE('',*,*,#1047,.T.);
#1049=EDGE_LOOP('',(#990,#999,#1007,#1016,#1024,#1033,#1041,#1048));
#1050=FACE_BOUND('',#1049,.T.);
#1051=DIRECTION('',(0.,1.,0.));
#1052=VECTOR('',#1051,1.);
#1053=CARTESIAN_POINT('',(115.1,0.,0.));
#1054=LINE('',#1053,#1052);
#1055=CARTESIAN_POINT('',(115.1,45.4500000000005,0.));
#1056=VERTEX_POINT('',#1055);
#1057=CARTESIAN_POINT('',(115.1,54.5500000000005,0.));
#1058=VERTEX_POINT('',#1057);
#1059=EDGE_CURVE('E643',#1056,#1058,#1054,.T.);
#1060=ORIENTED_EDGE('',*,*,#1059,.T.);
#1061=CARTESIAN_POINT('',(113.6,56.0500000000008,0.));
#1062=DIRECTION('',(0.,0.,1.));
#1063=DIRECTION('',(1.,0.,0.));
#1064=AXIS2_PLACEMENT_3D('',#1061,#1062,#1063);
#1065=CIRCLE('',#1064,2.12132034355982);
#1066=CARTESIAN_POINT('',(112.1,57.550000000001,0.));
#1067=VERTEX_POINT('',#1066);
#1068=EDGE_CURVE('E680',#1058,#1067,#1065,.T.);
#1069=ORIENTED_EDGE('',*,*,#1068,.T.);
#1070=DIRECTION('',(-1.,0.,0.));
#1071=VECTOR('',#1070,1.);
#1072=CARTESIAN_POINT('',(0.,57.5500000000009,0.));
#1073=LINE('',#1072,#1071);
#1074=CARTESIAN_POINT('',(103.,57.550000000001,0.));
#1075=VERTEX_POINT('',#1074);
#1076=EDGE_CURVE('E677',#1067,#1075,#1073,.T.);
#1077=ORIENTED_EDGE('',*,*,#1076,.T.);
#1078=CARTESIAN_POINT('',(101.5,56.0500000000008,0.));
#1079=DIRECTION('',(0.,0.,1.));
#1080=DIRECTION('',(1.,0.,0.));
#1081=AXIS2_PLACEMENT_3D('',#1078,#1079,#1080);
#1082=CIRCLE('',#1081,2.12132034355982);
#1083=CARTESIAN_POINT('',(100.,54.5500000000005,0.));
#1084=VERTEX_POINT('',#1083);
#1085=EDGE_CURVE('E675',#1084,#1075,#1082,.F.);
#1086=ORIENTED_EDGE('',*,*,#1085,.F.);
#1087=DIRECTION('',(0.,-1.,0.));
#1088=VECTOR('',#1087,1.);
#1089=CARTESIAN_POINT('',(100.,0.,0.));
#1090=LINE('',#1089,#1088);
#1091=CARTESIAN_POINT('',(100.,45.4500000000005,0.));
#1092=VERTEX_POINT('',#1091);
#1093=EDGE_CURVE('E672',#1084,#1092,#1090,.T.);
#1094=ORIENTED_EDGE('',*,*,#1093,.T.);
#1095=CARTESIAN_POINT('',(101.5,43.9500000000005,0.));
#1096=DIRECTION('',(0.,0.,1.));
#1097=DIRECTION('',(1.,0.,0.));
#1098=AXIS2_PLACEMENT_3D('',#1095,#1096,#1097);
#1099=CIRCLE('',#1098,2.12132034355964);
#1100=CARTESIAN_POINT('',(103.,42.4500000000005,0.));
#1101=VERTEX_POINT('',#1100);
#1102=EDGE_CURVE('E669',#1092,#1101,#1099,.T.);
#1103=ORIENTED_EDGE('',*,*,#1102,.T.);
#1104=DIRECTION('',(1.,0.,0.));
#1105=VECTOR('',#1104,1.);
#1106=CARTESIAN_POINT('',(0.,42.4500000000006,0.));
#1107=LINE('',#1106,#1105);
#1108=CARTESIAN_POINT('',(112.1,42.4500000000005,0.));
#1109=VERTEX_POINT('',#1108);
#1110=EDGE_CURVE('E666',#1101,#1109,#1107,.T.);
#1111=ORIENTED_EDGE('',*,*,#1110,.T.);
#1112=CARTESIAN_POINT('',(113.6,43.9500000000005,0.));
#1113=DIRECTION('',(0.,0.,1.));
#1114=DIRECTION('',(1.,0.,0.));
#1115=AXIS2_PLACEMENT_3D('',#1112,#1113,#1114);
#1116=CIRCLE('',#1115,2.12132034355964);
#1117=EDGE_CURVE('E625',#1109,#1056,#1116,.T.);
#1118=ORIENTED_EDGE('',*,*,#1117,.T.);
#1119=EDGE_LOOP('',(#1060,#1069,#1077,#1086,#1094,#1103,#1111,#1118));
#1120=FACE_BOUND('',#1119,.T.);
#1121=DIRECTION('',(0.,1.,0.));
#1122=VECTOR('',#1121,1.);
#1123=CARTESIAN_POINT('',(115.1,0.,0.));
#1124=LINE('',#1123,#1122);
#1125=CARTESIAN_POINT('',(115.1,15.35,0.));
#1126=VERTEX_POINT('',#1125);
#1127=CARTESIAN_POINT('',(115.1,24.45,0.));
#1128=VERTEX_POINT('',#1127);
#1129=EDGE_CURVE('E580',#1126,#1128,#1124,.T.);
#1130=ORIENTED_EDGE('',*,*,#1129,.T.);
#1131=CARTESIAN_POINT('',(113.6,25.9500000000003,0.));
#1132=DIRECTION('',(0.,0.,1.));
#1133=DIRECTION('',(1.,0.,0.));
#1134=AXIS2_PLACEMENT_3D('',#1131,#1132,#1133);
#1135=CIRCLE('',#1134,2.12132034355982);
#1136=CARTESIAN_POINT('',(112.1,27.4500000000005,0.));
#1137=VERTEX_POINT('',#1136);
#1138=EDGE_CURVE('E617',#1128,#1137,#1135,.T.);
#1139=ORIENTED_EDGE('',*,*,#1138,.T.);
#1140=DIRECTION('',(-1.,0.,0.));
#1141=VECTOR('',#1140,1.);
#1142=CARTESIAN_POINT('',(0.,27.4500000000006,0.));
#1143=LINE('',#1142,#1141);
#1144=CARTESIAN_POINT('',(103.,27.4500000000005,0.));
#1145=VERTEX_POINT('',#1144);
#1146=EDGE_CURVE('E614',#1137,#1145,#1143,.T.);
#1147=ORIENTED_EDGE('',*,*,#1146,.T.);
#1148=CARTESIAN_POINT('',(101.5,25.9500000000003,0.));
#1149=DIRECTION('',(0.,0.,1.));
#1150=DIRECTION('',(1.,0.,0.));
#1151=AXIS2_PLACEMENT_3D('',#1148,#1149,#1150);
#1152=CIRCLE('',#1151,2.12132034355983);
#1153=CARTESIAN_POINT('',(100.,24.45,0.));
#1154=VERTEX_POINT('',#1153);
#1155=EDGE_CURVE('E612',#1154,#1145,#1152,.F.);
#1156=ORIENTED_EDGE('',*,*,#1155,.F.);
#1157=DIRECTION('',(0.,-1.,0.));
#1158=VECTOR('',#1157,1.);
#1159=CARTESIAN_POINT('',(100.,0.,0.));
#1160=LINE('',#1159,#1158);
#1161=CARTESIAN_POINT('',(100.,15.35,0.));
#1162=VERTEX_POINT('',#1161);
#1163=EDGE_CURVE('E609',#1154,#1162,#1160,.T.);
#1164=ORIENTED_EDGE('',*,*,#1163,.T.);
#1165=CARTESIAN_POINT('',(101.5,13.85,0.));
#1166=DIRECTION('',(0.,0.,1.));
#1167=DIRECTION('',(1.,0.,0.));
#1168=AXIS2_PLACEMENT_3D('',#1165,#1166,#1167);
#1169=CIRCLE('',#1168,2.12132034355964);
#1170=CARTESIAN_POINT('',(103.,12.35,0.));
#1171=VERTEX_POINT('',#1170);
#1172=EDGE_CURVE('E606',#1162,#1171,#1169,.T.);
#1173=ORIENTED_EDGE('',*,*,#1172,.T.);
#1174=DIRECTION('',(1.,0.,0.));
#1175=VECTOR('',#1174,1.);
#1176=CARTESIAN_POINT('',(0.,12.35,0.));
#1177=LINE('',#1176,#1175);
#1178=CARTESIAN_POINT('',(112.1,12.35,0.));
#1179=VERTEX_POINT('',#1178);
#1180=EDGE_CURVE('E603',#1171,#1179,#1177,.T.);
#1181=ORIENTED_EDGE('',*,*,#1180,.T.);
#1182=CARTESIAN_POINT('',(113.6,13.85,0.));
#1183=DIRECTION('',(0.,0.,1.));
#1184=DIRECTION('',(1.,0.,0.));
#1185=AXIS2_PLACEMENT_3D('',#1182,#1183,#1184);
#1186=CIRCLE('',#1185,2.12132034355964);
#1187=EDGE_CURVE('E562',#1179,#1126,#1186,.T.);
#1188=ORIENTED_EDGE('',*,*,#1187,.T.);
#1189=EDGE_LOOP('',(#1130,#1139,#1147,#1156,#1164,#1173,#1181,#1188));
#1190=FACE_BOUND('',#1189,.T.);
#1191=CARTESIAN_POINT('',(45.5,69.5,0.));
#1192=DIRECTION('',(0.,0.,1.));
#1193=DIRECTION('',(1.,0.,0.));
#1194=AXIS2_PLACEMENT_3D('',#1191,#1192,#1193);
#1195=CIRCLE('',#1194,12.);
#1196=CARTESIAN_POINT('',(57.4999999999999,69.5,0.));
#1197=VERTEX_POINT('',#1196);
#1198=EDGE_CURVE('E550',#1197,#1197,#1195,.T.);
#1199=ORIENTED_EDGE('',*,*,#1198,.T.);
#1200=EDGE_LOOP('',(#1199));
#1201=FACE_BOUND('',#1200,.T.);
#1202=CARTESIAN_POINT('',(30.,54.,0.));
#1203=DIRECTION('',(0.,0.,1.));
#1204=DIRECTION('',(1.,0.,0.));
#1205=AXIS2_PLACEMENT_3D('',#1202,#1203,#1204);
#1206=CIRCLE('',#1205,3.);
#1207=CARTESIAN_POINT('',(33.,54.,0.));
#1208=VERTEX_POINT('',#1207);
#1209=EDGE_CURVE('E544',#1208,#1208,#1206,.T.);
#1210=ORIENTED_EDGE('',*,*,#1209,.T.);
#1211=EDGE_LOOP('',(#1210));
#1212=FACE_BOUND('',#1211,.T.);
#1213=CARTESIAN_POINT('',(30.,85.,0.));
#1214=DIRECTION('',(0.,0.,1.));
#1215=DIRECTION('',(1.,0.,0.));
#1216=AXIS2_PLACEMENT_3D('',#1213,#1214,#1215);
#1217=CIRCLE('',#1216,3.);
#1218=CARTESIAN_POINT('',(33.,85.,0.));
#1219=VERTEX_POINT('',#1218);
#1220=EDGE_CURVE('E538',#1219,#1219,#1217,.T.);
#1221=ORIENTED_EDGE('',*,*,#1220,.T.);
#1222=EDGE_LOOP('',(#1221));
#1223=FACE_BOUND('',#1222,.T.);
#1224=CARTESIAN_POINT('',(61.,85.,0.));
#1225=DIRECTION('',(0.,0.,1.));
#1226=DIRECTION('',(1.,0.,0.));
#1227=AXIS2_PLACEMENT_3D('',#1224,#1225,#1226);
#1228=CIRCLE('',#1227,3.00000000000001);
#1229=CARTESIAN_POINT('',(64.,85.,0.));
#1230=VERTEX_POINT('',#1229);
#1231=EDGE_CURVE('E532',#1230,#1230,#1228,.T.);
#1232=ORIENTED_EDGE('',*,*,#1231,.T.);
#1233=EDGE_LOOP('',(#1232));
#1234=FACE_BOUND('',#1233,.T.);
#1235=CARTESIAN_POINT('',(61.,54.,0.));
#1236=DIRECTION('',(0.,0.,1.));
#1237=DIRECTION('',(1.,0.,0.));
#1238=AXIS2_PLACEMENT_3D('',#1235,#1236,#1237);
#1239=CIRCLE('',#1238,3.00000000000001);
#1240=CARTESIAN_POINT('',(64.,54.,0.));
#1241=VERTEX_POINT('',#1240);
#1242=EDGE_CURVE('E507',#1241,#1241,#1239,.T.);
#1243=ORIENTED_EDGE('',*,*,#1242,.T.);
#1244=EDGE_LOOP('',(#1243));
#1245=FACE_BOUND('',#1244,.T.);
#1246=DIRECTION('',(-1.,0.,0.));
#1247=VECTOR('',#1246,1.);
#1248=CARTESIAN_POINT('',(497.,57.5500000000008,0.));
#1249=LINE('',#1248,#1247);
#1250=CARTESIAN_POINT('',(497.,57.5500000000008,0.));
#1251=VERTEX_POINT('',#1250);
#1252=CARTESIAN_POINT('',(487.9,57.5500000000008,0.));
#1253=VERTEX_POINT('',#1252);
#1254=EDGE_CURVE('E525',#1251,#1253,#1249,.T.);
#1255=ORIENTED_EDGE('',*,*,#1254,.T.);
#1256=CARTESIAN_POINT('',(486.4,56.0500000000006,0.));
#1257=DIRECTION('',(0.,0.,-1.));
#1258=DIRECTION('',(-1.,0.,0.));
#1259=AXIS2_PLACEMENT_3D('',#1256,#1257,#1258);
#1260=CIRCLE('',#1259,2.12132034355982);
#1261=CARTESIAN_POINT('',(484.9,54.5500000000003,0.));
#1262=VERTEX_POINT('',#1261);
#1263=EDGE_CURVE('E486',#1262,#1253,#1260,.T.);
#1264=ORIENTED_EDGE('',*,*,#1263,.F.);
#1265=DIRECTION('',(0.,-1.,0.));
#1266=VECTOR('',#1265,1.);
#1267=CARTESIAN_POINT('',(484.9,54.5500000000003,0.));
#1268=LINE('',#1267,#1266);
#1269=CARTESIAN_POINT('',(484.9,45.4500000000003,0.));
#1270=VERTEX_POINT('',#1269);
#1271=EDGE_CURVE('E481',#1262,#1270,#1268,.T.);
#1272=ORIENTED_EDGE('',*,*,#1271,.T.);
#1273=CARTESIAN_POINT('',(486.4,43.9500000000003,0.));
#1274=DIRECTION('',(0.,0.,1.));
#1275=DIRECTION('',(1.,0.,0.));
#1276=AXIS2_PLACEMENT_3D('',#1273,#1274,#1275);
#1277=CIRCLE('',#1276,2.12132034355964);
#1278=CARTESIAN_POINT('',(487.9,42.4500000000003,0.));
#1279=VERTEX_POINT('',#1278);
#1280=EDGE_CURVE('E510',#1270,#1279,#1277,.T.);
#1281=ORIENTED_EDGE('',*,*,#1280,.T.);
#1282=DIRECTION('',(1.,0.,0.));
#1283=VECTOR('',#1282,1.);
#1284=CARTESIAN_POINT('',(487.9,42.4500000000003,0.));
#1285=LINE('',#1284,#1283);
#1286=CARTESIAN_POINT('',(497.,42.4500000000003,0.));
#1287=VERTEX_POINT('',#1286);
#1288=EDGE_CURVE('E513',#1279,#1287,#1285,.T.);
#1289=ORIENTED_EDGE('',*,*,#1288,.T.);
#1290=CARTESIAN_POINT('',(498.5,43.9500000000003,0.));
#1291=DIRECTION('',(0.,0.,1.));
#1292=DIRECTION('',(1.,0.,0.));
#1293=AXIS2_PLACEMENT_3D('',#1290,#1291,#1292);
#1294=CIRCLE('',#1293,2.12132034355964);
#1295=CARTESIAN_POINT('',(500.,45.4500000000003,0.));
#1296=VERTEX_POINT('',#1295);
#1297=EDGE_CURVE('E516',#1287,#1296,#1294,.T.);
#1298=ORIENTED_EDGE('',*,*,#1297,.T.);
#1299=DIRECTION('',(0.,1.,0.));
#1300=VECTOR('',#1299,1.);
#1301=CARTESIAN_POINT('',(500.,45.4500000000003,0.));
#1302=LINE('',#1301,#1300);
#1303=CARTESIAN_POINT('',(500.,54.5500000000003,0.));
#1304=VERTEX_POINT('',#1303);
#1305=EDGE_CURVE('E519',#1296,#1304,#1302,.T.);
#1306=ORIENTED_EDGE('',*,*,#1305,.T.);
#1307=CARTESIAN_POINT('',(498.5,56.0500000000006,0.));
#1308=DIRECTION('',(0.,0.,1.));
#1309=DIRECTION('',(1.,0.,0.));
#1310=AXIS2_PLACEMENT_3D('',#1307,#1308,#1309);
#1311=CIRCLE('',#1310,2.12132034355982);
#1312=EDGE_CURVE('E522',#1304,#1251,#1311,.T.);
#1313=ORIENTED_EDGE('',*,*,#1312,.T.);
#1314=EDGE_LOOP('',(#1255,#1264,#1272,#1281,#1289,#1298,#1306,#1313));
#1315=FACE_BOUND('',#1314,.T.);
#1316=ADVANCED_FACE('F893',(#694,#705,#716,#727,#738,#808,#910,#980,#1050,#1120,#1190,#1201,
#1212,#1223,#1234,#1245,#1315),#683,.T.);
#1317=CARTESIAN_POINT('',(150.,0.,15.));
#1318=DIRECTION('',(0.,1.,0.));
#1319=DIRECTION('',(-1.,0.,0.));
#1320=AXIS2_PLACEMENT_3D('',#1317,#1318,#1319);
#1321=PLANE('',#1320);
#1322=ORIENTED_EDGE('',*,*,#885,.T.);
#1323=DIRECTION('',(0.,0.,-1.));
#1324=VECTOR('',#1323,1.);
#1325=CARTESIAN_POINT('',(147.,0.,15.));
#1326=LINE('',#1325,#1324);
#1327=EDGE_CURVE('E884',#876,#227,#1326,.F.);
#1328=ORIENTED_EDGE('',*,*,#1327,.T.);
#1329=ORIENTED_EDGE('',*,*,#228,.F.);
#1330=DIRECTION('',(0.,0.,-1.));
#1331=VECTOR('',#1330,1.);
#1332=CARTESIAN_POINT('',(0.,0.,15.));
#1333=LINE('',#1332,#1331);
#1334=EDGE_CURVE('E830',#219,#884,#1333,.T.);
#1335=ORIENTED_EDGE('',*,*,#1334,.T.);
#1336=EDGE_LOOP('',(#1322,#1328,#1329,#1335));
#1337=FACE_BOUND('',#1336,.T.);
#1338=ADVANCED_FACE('F943',(#1337),#1321,.F.);
#1339=CARTESIAN_POINT('',(150.,9.99999999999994,15.));
#1340=DIRECTION('',(-1.,0.,0.));
#1341=DIRECTION('',(0.,-1.,0.));
#1342=AXIS2_PLACEMENT_3D('',#1339,#1340,#1341);
#1343=PLANE('',#1342);
#1344=ORIENTED_EDGE('',*,*,#868,.T.);
#1345=DIRECTION('',(0.,0.,-1.));
#1346=VECTOR('',#1345,1.);
#1347=CARTESIAN_POINT('',(150.,6.99999999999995,15.));
#1348=LINE('',#1347,#1346);
#1349=EDGE_CURVE('E882',#859,#244,#1348,.F.);
#1350=ORIENTED_EDGE('',*,*,#1349,.T.);
#1351=ORIENTED_EDGE('',*,*,#245,.F.);
#1352=DIRECTION('',(0.,0.,-1.));
#1353=VECTOR('',#1352,1.);
#1354=CARTESIAN_POINT('',(150.,3.,15.));
#1355=LINE('',#1354,#1353);
#1356=EDGE_CURVE('E879',#236,#867,#1355,.T.);
#1357=ORIENTED_EDGE('',*,*,#1356,.T.);
#1358=EDGE_LOOP('',(#1344,#1350,#1351,#1357));
#1359=FACE_BOUND('',#1358,.T.);
#1360=ADVANCED_FACE('F899',(#1359),#1343,.F.);
#1361=CARTESIAN_POINT('',(450.,9.99999999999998,15.));
#1362=DIRECTION('',(0.,1.,0.));
#1363=DIRECTION('',(-1.,0.,0.));
#1364=AXIS2_PLACEMENT_3D('',#1361,#1362,#1363);
#1365=PLANE('',#1364);
#1366=ORIENTED_EDGE('',*,*,#851,.T.);
#1367=DIRECTION('',(0.,0.,-1.));
#1368=VECTOR('',#1367,1.);
#1369=CARTESIAN_POINT('',(447.,9.99999999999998,15.));
#1370=LINE('',#1369,#1368);
#1371=EDGE_CURVE('E50',#842,#261,#1370,.F.);
#1372=ORIENTED_EDGE('',*,*,#1371,.T.);
#1373=ORIENTED_EDGE('',*,*,#262,.F.);
#1374=DIRECTION('',(0.,0.,-1.));
#1375=VECTOR('',#1374,1.);
#1376=CARTESIAN_POINT('',(153.,9.99999999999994,0.));
#1377=LINE('',#1376,#1375);
#1378=EDGE_CURVE('E875',#253,#850,#1377,.T.);
#1379=ORIENTED_EDGE('',*,*,#1378,.T.);
#1380=EDGE_LOOP('',(#1366,#1372,#1373,#1379));
#1381=FACE_BOUND('',#1380,.T.);
#1382=ADVANCED_FACE('F903',(#1381),#1365,.F.);
#1383=CARTESIAN_POINT('',(450.,0.,15.));
#1384=DIRECTION('',(1.,0.,0.));
#1385=DIRECTION('',(0.,0.,-1.));
#1386=AXIS2_PLACEMENT_3D('',#1383,#1384,#1385);
#1387=PLANE('',#1386);
#1388=ORIENTED_EDGE('',*,*,#834,.T.);
#1389=DIRECTION('',(0.,0.,-1.));
#1390=VECTOR('',#1389,1.);
#1391=CARTESIAN_POINT('',(450.,2.99999999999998,15.));
#1392=LINE('',#1391,#1390);
#1393=EDGE_CURVE('E869',#825,#178,#1392,.F.);
#1394=ORIENTED_EDGE('',*,*,#1393,.T.);
#1395=ORIENTED_EDGE('',*,*,#179,.F.);
#1396=DIRECTION('',(0.,0.,-1.));
#1397=VECTOR('',#1396,1.);
#1398=CARTESIAN_POINT('',(450.,6.99999999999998,0.));
#1399=LINE('',#1398,#1397);
#1400=EDGE_CURVE('E866',#176,#833,#1399,.T.);
#1401=ORIENTED_EDGE('',*,*,#1400,.T.);
#1402=EDGE_LOOP('',(#1388,#1394,#1395,#1401));
#1403=FACE_BOUND('',#1402,.T.);
#1404=ADVANCED_FACE('F912',(#1403),#1387,.F.);
#1405=CARTESIAN_POINT('',(600.,0.,15.));
#1406=DIRECTION('',(0.,1.,0.));
#1407=DIRECTION('',(-1.,0.,0.));
#1408=AXIS2_PLACEMENT_3D('',#1405,#1406,#1407);
#1409=PLANE('',#1408);
#1410=ORIENTED_EDGE('',*,*,#196,.F.);
#1411=DIRECTION('',(0.,0.,-1.));
#1412=VECTOR('',#1411,1.);
#1413=CARTESIAN_POINT('',(453.,0.,15.));
#1414=LINE('',#1413,#1412);
#1415=EDGE_CURVE('E859',#187,#814,#1414,.T.);
#1416=ORIENTED_EDGE('',*,*,#1415,.T.);
#1417=ORIENTED_EDGE('',*,*,#817,.T.);
#1418=DIRECTION('',(0.,0.,-1.));
#1419=VECTOR('',#1418,1.);
#1420=CARTESIAN_POINT('',(600.,0.,15.));
#1421=LINE('',#1420,#1419);
#1422=EDGE_CURVE('E856',#195,#816,#1421,.T.);
#1423=ORIENTED_EDGE('',*,*,#1422,.F.);
#1424=EDGE_LOOP('',(#1410,#1416,#1417,#1423));
#1425=FACE_BOUND('',#1424,.T.);
#1426=ADVANCED_FACE('F921',(#1425),#1409,.F.);
#1427=CARTESIAN_POINT('',(600.,0.,15.));
#1428=DIRECTION('',(-1.,0.,0.));
#1429=DIRECTION('',(0.,0.,1.));
#1430=AXIS2_PLACEMENT_3D('',#1427,#1428,#1429);
#1431=PLANE('',#1430);
#1432=ORIENTED_EDGE('',*,*,#907,.T.);
#1433=DIRECTION('',(0.,0.,-1.));
#1434=VECTOR('',#1433,1.);
#1435=CARTESIAN_POINT('',(600.,100.,15.));
#1436=LINE('',#1435,#1434);
#1437=EDGE_CURVE('E853',#203,#900,#1436,.T.);
#1438=ORIENTED_EDGE('',*,*,#1437,.F.);
#1439=ORIENTED_EDGE('',*,*,#204,.F.);
#1440=ORIENTED_EDGE('',*,*,#1422,.T.);
#1441=EDGE_LOOP('',(#1432,#1438,#1439,#1440));
#1442=FACE_BOUND('',#1441,.T.);
#1443=ADVANCED_FACE('F928',(#1442),#1431,.F.);
#1444=CARTESIAN_POINT('',(0.,100.,15.));
#1445=DIRECTION('',(0.,-1.,0.));
#1446=DIRECTION('',(0.,0.,-1.));
#1447=AXIS2_PLACEMENT_3D('',#1444,#1445,#1446);
#1448=PLANE('',#1447);
#1449=ORIENTED_EDGE('',*,*,#901,.T.);
#1450=DIRECTION('',(0.,0.,-1.));
#1451=VECTOR('',#1450,1.);
#1452=CARTESIAN_POINT('',(0.,100.,15.));
#1453=LINE('',#1452,#1451);
#1454=EDGE_CURVE('E850',#211,#892,#1453,.T.);
#1455=ORIENTED_EDGE('',*,*,#1454,.F.);
#1456=ORIENTED_EDGE('',*,*,#212,.F.);
#1457=ORIENTED_EDGE('',*,*,#1437,.T.);
#1458=EDGE_LOOP('',(#1449,#1455,#1456,#1457));
#1459=FACE_BOUND('',#1458,.T.);
#1460=ADVANCED_FACE('F931',(#1459),#1448,.F.);
#1461=CARTESIAN_POINT('',(0.,0.,15.));
#1462=DIRECTION('',(1.,0.,0.));
#1463=DIRECTION('',(0.,0.,-1.));
#1464=AXIS2_PLACEMENT_3D('',#1461,#1462,#1463);
#1465=PLANE('',#1464);
#1466=ORIENTED_EDGE('',*,*,#893,.T.);
#1467=ORIENTED_EDGE('',*,*,#1334,.F.);
#1468=ORIENTED_EDGE('',*,*,#220,.F.);
#1469=ORIENTED_EDGE('',*,*,#1454,.T.);
#1470=EDGE_LOOP('',(#1466,#1467,#1468,#1469));
#1471=FACE_BOUND('',#1470,.T.);
#1472=ADVANCED_FACE('F936',(#1471),#1465,.F.);
#1473=CARTESIAN_POINT('',(500.,0.,0.));
#1474=DIRECTION('',(1.,0.,0.));
#1475=DIRECTION('',(0.,0.,-1.));
#1476=AXIS2_PLACEMENT_3D('',#1473,#1474,#1475);
#1477=PLANE('',#1476);
#1478=ORIENTED_EDGE('',*,*,#290,.T.);
#1479=DIRECTION('',(0.,0.,1.));
#1480=VECTOR('',#1479,1.);
#1481=CARTESIAN_POINT('',(500.,84.6500000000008,0.));
#1482=LINE('',#1481,#1480);
#1483=EDGE_CURVE('E772',#918,#279,#1482,.T.);
#1484=ORIENTED_EDGE('',*,*,#1483,.F.);
#1485=ORIENTED_EDGE('',*,*,#919,.F.);
#1486=DIRECTION('',(0.,0.,1.));
#1487=VECTOR('',#1486,1.);
#1488=CARTESIAN_POINT('',(500.,75.5500000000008,0.));
#1489=LINE('',#1488,#1487);
#1490=EDGE_CURVE('E794',#916,#289,#1489,.T.);
#1491=ORIENTED_EDGE('',*,*,#1490,.T.);
#1492=EDGE_LOOP('',(#1478,#1484,#1485,#1491));
#1493=FACE_BOUND('',#1492,.T.);
#1494=ADVANCED_FACE('F962',(#1493),#1477,.F.);
#1495=CARTESIAN_POINT('',(498.5,74.0500000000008,0.));
#1496=DIRECTION('',(0.,0.,1.));
#1497=DIRECTION('',(1.,0.,0.));
#1498=AXIS2_PLACEMENT_3D('',#1495,#1496,#1497);
#1499=CYLINDRICAL_SURFACE('',#1498,2.12132034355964);
#1500=ORIENTED_EDGE('',*,*,#299,.T.);
#1501=ORIENTED_EDGE('',*,*,#1490,.F.);
#1502=ORIENTED_EDGE('',*,*,#977,.F.);
#1503=DIRECTION('',(0.,0.,1.));
#1504=VECTOR('',#1503,1.);
#1505=CARTESIAN_POINT('',(497.,72.5500000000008,0.));
#1506=LINE('',#1505,#1504);
#1507=EDGE_CURVE('E797',#969,#298,#1506,.T.);
#1508=ORIENTED_EDGE('',*,*,#1507,.T.);
#1509=EDGE_LOOP('',(#1500,#1501,#1502,#1508));
#1510=FACE_BOUND('',#1509,.T.);
#1511=ADVANCED_FACE('F1007',(#1510),#1499,.F.);
#1512=CARTESIAN_POINT('',(-1.10641044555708E-13,72.5500000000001,0.));
#1513=DIRECTION('',(0.,-1.,0.));
#1514=DIRECTION('',(1.,0.,0.));
#1515=AXIS2_PLACEMENT_3D('',#1512,#1513,#1514);
#1516=PLANE('',#1515);
#1517=ORIENTED_EDGE('',*,*,#307,.T.);
#1518=ORIENTED_EDGE('',*,*,#1507,.F.);
#1519=ORIENTED_EDGE('',*,*,#970,.F.);
#1520=DIRECTION('',(0.,0.,1.));
#1521=VECTOR('',#1520,1.);
#1522=CARTESIAN_POINT('',(487.9,72.5500000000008,0.));
#1523=LINE('',#1522,#1521);
#1524=EDGE_CURVE('E799',#961,#306,#1523,.T.);
#1525=ORIENTED_EDGE('',*,*,#1524,.T.);
#1526=EDGE_LOOP('',(#1517,#1518,#1519,#1525));
#1527=FACE_BOUND('',#1526,.T.);
#1528=ADVANCED_FACE('F1014',(#1527),#1516,.F.);
#1529=CARTESIAN_POINT('',(486.4,74.0500000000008,0.));
#1530=DIRECTION('',(0.,0.,1.));
#1531=DIRECTION('',(1.,0.,0.));
#1532=AXIS2_PLACEMENT_3D('',#1529,#1530,#1531);
#1533=CYLINDRICAL_SURFACE('',#1532,2.12132034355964);
#1534=ORIENTED_EDGE('',*,*,#316,.T.);
#1535=ORIENTED_EDGE('',*,*,#1524,.F.);
#1536=ORIENTED_EDGE('',*,*,#962,.F.);
#1537=DIRECTION('',(0.,0.,1.));
#1538=VECTOR('',#1537,1.);
#1539=CARTESIAN_POINT('',(484.9,75.5500000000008,0.));
#1540=LINE('',#1539,#1538);
#1541=EDGE_CURVE('E801',#952,#315,#1540,.T.);
#1542=ORIENTED_EDGE('',*,*,#1541,.T.);
#1543=EDGE_LOOP('',(#1534,#1535,#1536,#1542));
#1544=FACE_BOUND('',#1543,.T.);
#1545=ADVANCED_FACE('F1022',(#1544),#1533,.F.);
#1546=CARTESIAN_POINT('',(484.9,-2.95795134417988E-12,0.));
#1547=DIRECTION('',(-1.,0.,0.));
#1548=DIRECTION('',(0.,-1.,0.));
#1549=AXIS2_PLACEMENT_3D('',#1546,#1547,#1548);
#1550=PLANE('',#1549);
#1551=ORIENTED_EDGE('',*,*,#324,.T.);
#1552=ORIENTED_EDGE('',*,*,#1541,.F.);
#1553=ORIENTED_EDGE('',*,*,#953,.F.);
#1554=DIRECTION('',(0.,0.,1.));
#1555=VECTOR('',#1554,1.);
#1556=CARTESIAN_POINT('',(484.9,84.6500000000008,0.));
#1557=LINE('',#1556,#1555);
#1558=EDGE_CURVE('E803',#944,#323,#1557,.T.);
#1559=ORIENTED_EDGE('',*,*,#1558,.T.);
#1560=EDGE_LOOP('',(#1551,#1552,#1553,#1559));
#1561=FACE_BOUND('',#1560,.T.);
#1562=ADVANCED_FACE('F1030',(#1561),#1550,.F.);
#1563=CARTESIAN_POINT('',(486.4,86.1500000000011,0.));
#1564=DIRECTION('',(0.,0.,1.));
#1565=DIRECTION('',(1.,0.,0.));
#1566=AXIS2_PLACEMENT_3D('',#1563,#1564,#1565);
#1567=CYLINDRICAL_SURFACE('',#1566,2.12132034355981);
#1568=ORIENTED_EDGE('',*,*,#333,.F.);
#1569=ORIENTED_EDGE('',*,*,#1558,.F.);
#1570=ORIENTED_EDGE('',*,*,#945,.T.);
#1571=DIRECTION('',(0.,0.,1.));
#1572=VECTOR('',#1571,1.);
#1573=CARTESIAN_POINT('',(487.9,87.6500000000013,0.));
#1574=LINE('',#1573,#1572);
#1575=EDGE_CURVE('E805',#935,#332,#1574,.T.);
#1576=ORIENTED_EDGE('',*,*,#1575,.T.);
#1577=EDGE_LOOP('',(#1568,#1569,#1570,#1576));
#1578=FACE_BOUND('',#1577,.T.);
#1579=ADVANCED_FACE('F1038',(#1578),#1567,.F.);
#1580=CARTESIAN_POINT('',(0.,87.6500000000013,0.));
#1581=DIRECTION('',(0.,1.,0.));
#1582=DIRECTION('',(0.,0.,1.));
#1583=AXIS2_PLACEMENT_3D('',#1580,#1581,#1582);
#1584=PLANE('',#1583);
#1585=ORIENTED_EDGE('',*,*,#339,.T.);
#1586=ORIENTED_EDGE('',*,*,#1575,.F.);
#1587=ORIENTED_EDGE('',*,*,#936,.F.);
#1588=DIRECTION('',(0.,0.,1.));
#1589=VECTOR('',#1588,1.);
#1590=CARTESIAN_POINT('',(497.,87.6500000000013,0.));
#1591=LINE('',#1590,#1589);
#1592=EDGE_CURVE('E807',#927,#281,#1591,.T.);
#1593=ORIENTED_EDGE('',*,*,#1592,.T.);
#1594=EDGE_LOOP('',(#1585,#1586,#1587,#1593));
#1595=FACE_BOUND('',#1594,.T.);
#1596=ADVANCED_FACE('F1046',(#1595),#1584,.F.);
#1597=CARTESIAN_POINT('',(498.5,86.1500000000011,0.));
#1598=DIRECTION('',(0.,0.,1.));
#1599=DIRECTION('',(1.,0.,0.));
#1600=AXIS2_PLACEMENT_3D('',#1597,#1598,#1599);
#1601=CYLINDRICAL_SURFACE('',#1600,2.12132034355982);
#1602=ORIENTED_EDGE('',*,*,#282,.T.);
#1603=ORIENTED_EDGE('',*,*,#1592,.F.);
#1604=ORIENTED_EDGE('',*,*,#928,.F.);
#1605=ORIENTED_EDGE('',*,*,#1483,.T.);
#1606=EDGE_LOOP('',(#1602,#1603,#1604,#1605));
#1607=FACE_BOUND('',#1606,.T.);
#1608=ADVANCED_FACE('F1054',(#1607),#1601,.F.);
#1609=CARTESIAN_POINT('',(115.1,0.,0.));
#1610=DIRECTION('',(1.,0.,0.));
#1611=DIRECTION('',(0.,0.,-1.));
#1612=AXIS2_PLACEMENT_3D('',#1609,#1610,#1611);
#1613=PLANE('',#1612);
#1614=ORIENTED_EDGE('',*,*,#360,.T.);
#1615=DIRECTION('',(0.,0.,1.));
#1616=VECTOR('',#1615,1.);
#1617=CARTESIAN_POINT('',(115.1,84.650000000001,0.));
#1618=LINE('',#1617,#1616);
#1619=EDGE_CURVE('E685',#988,#349,#1618,.T.);
#1620=ORIENTED_EDGE('',*,*,#1619,.F.);
#1621=ORIENTED_EDGE('',*,*,#989,.F.);
#1622=DIRECTION('',(0.,0.,1.));
#1623=VECTOR('',#1622,1.);
#1624=CARTESIAN_POINT('',(115.1,75.550000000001,0.));
#1625=LINE('',#1624,#1623);
#1626=EDGE_CURVE('E663',#986,#359,#1625,.T.);
#1627=ORIENTED_EDGE('',*,*,#1626,.T.);
#1628=EDGE_LOOP('',(#1614,#1620,#1621,#1627));
#1629=FACE_BOUND('',#1628,.T.);
#1630=ADVANCED_FACE('F1062',(#1629),#1613,.F.);
#1631=CARTESIAN_POINT('',(113.6,74.050000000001,0.));
#1632=DIRECTION('',(0.,0.,1.));
#1633=DIRECTION('',(1.,0.,0.));
#1634=AXIS2_PLACEMENT_3D('',#1631,#1632,#1633);
#1635=CYLINDRICAL_SURFACE('',#1634,2.12132034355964);
#1636=ORIENTED_EDGE('',*,*,#369,.T.);
#1637=ORIENTED_EDGE('',*,*,#1626,.F.);
#1638=ORIENTED_EDGE('',*,*,#1047,.F.);
#1639=DIRECTION('',(0.,0.,1.));
#1640=VECTOR('',#1639,1.);
#1641=CARTESIAN_POINT('',(112.1,72.550000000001,0.));
#1642=LINE('',#1641,#1640);
#1643=EDGE_CURVE('E699',#1039,#368,#1642,.T.);
#1644=ORIENTED_EDGE('',*,*,#1643,.T.);
#1645=EDGE_LOOP('',(#1636,#1637,#1638,#1644));
#1646=FACE_BOUND('',#1645,.T.);
#1647=ADVANCED_FACE('F1069',(#1646),#1635,.F.);
#1648=CARTESIAN_POINT('',(-1.10641044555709E-13,72.5500000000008,0.));
#1649=DIRECTION('',(0.,-1.,0.));
#1650=DIRECTION('',(1.,0.,0.));
#1651=AXIS2_PLACEMENT_3D('',#1648,#1649,#1650);
#1652=PLANE('',#1651);
#1653=ORIENTED_EDGE('',*,*,#377,.T.);
#1654=ORIENTED_EDGE('',*,*,#1643,.F.);
#1655=ORIENTED_EDGE('',*,*,#1040,.F.);
#1656=DIRECTION('',(0.,0.,1.));
#1657=VECTOR('',#1656,1.);
#1658=CARTESIAN_POINT('',(103.,72.550000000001,0.));
#1659=LINE('',#1658,#1657);
#1660=EDGE_CURVE('E697',#1031,#376,#1659,.T.);
#1661=ORIENTED_EDGE('',*,*,#1660,.T.);
#1662=EDGE_LOOP('',(#1653,#1654,#1655,#1661));
#1663=FACE_BOUND('',#1662,.T.);
#1664=ADVANCED_FACE('F1077',(#1663),#1652,.F.);
#1665=CARTESIAN_POINT('',(101.5,74.050000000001,0.));
#1666=DIRECTION('',(0.,0.,1.));
#1667=DIRECTION('',(1.,0.,0.));
#1668=AXIS2_PLACEMENT_3D('',#1665,#1666,#1667);
#1669=CYLINDRICAL_SURFACE('',#1668,2.12132034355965);
#1670=ORIENTED_EDGE('',*,*,#386,.T.);
#1671=ORIENTED_EDGE('',*,*,#1660,.F.);
#1672=ORIENTED_EDGE('',*,*,#1032,.F.);
#1673=DIRECTION('',(0.,0.,1.));
#1674=VECTOR('',#1673,1.);
#1675=CARTESIAN_POINT('',(100.,75.550000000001,0.));
#1676=LINE('',#1675,#1674);
#1677=EDGE_CURVE('E695',#1022,#385,#1676,.T.);
#1678=ORIENTED_EDGE('',*,*,#1677,.T.);
#1679=EDGE_LOOP('',(#1670,#1671,#1672,#1678));
#1680=FACE_BOUND('',#1679,.T.);
#1681=ADVANCED_FACE('F1085',(#1680),#1669,.F.);
#1682=CARTESIAN_POINT('',(100.,0.,0.));
#1683=DIRECTION('',(-1.,0.,0.));
#1684=DIRECTION('',(0.,0.,1.));
#1685=AXIS2_PLACEMENT_3D('',#1682,#1683,#1684);
#1686=PLANE('',#1685);
#1687=ORIENTED_EDGE('',*,*,#394,.T.);
#1688=ORIENTED_EDGE('',*,*,#1677,.F.);
#1689=ORIENTED_EDGE('',*,*,#1023,.F.);
#1690=DIRECTION('',(0.,0.,1.));
#1691=VECTOR('',#1690,1.);
#1692=CARTESIAN_POINT('',(100.,84.650000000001,0.));
#1693=LINE('',#1692,#1691);
#1694=EDGE_CURVE('E693',#1014,#393,#1693,.T.);
#1695=ORIENTED_EDGE('',*,*,#1694,.T.);
#1696=EDGE_LOOP('',(#1687,#1688,#1689,#1695));
#1697=FACE_BOUND('',#1696,.T.);
#1698=ADVANCED_FACE('F1093',(#1697),#1686,.F.);
#1699=CARTESIAN_POINT('',(101.5,86.1500000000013,0.));
#1700=DIRECTION('',(0.,0.,1.));
#1701=DIRECTION('',(1.,0.,0.));
#1702=AXIS2_PLACEMENT_3D('',#1699,#1700,#1701);
#1703=CYLINDRICAL_SURFACE('',#1702,2.12132034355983);
#1704=ORIENTED_EDGE('',*,*,#403,.F.);
#1705=ORIENTED_EDGE('',*,*,#1694,.F.);
#1706=ORIENTED_EDGE('',*,*,#1015,.T.);
#1707=DIRECTION('',(0.,0.,1.));
#1708=VECTOR('',#1707,1.);
#1709=CARTESIAN_POINT('',(103.,87.6500000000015,0.));
#1710=LINE('',#1709,#1708);
#1711=EDGE_CURVE('E691',#1005,#402,#1710,.T.);
#1712=ORIENTED_EDGE('',*,*,#1711,.T.);
#1713=EDGE_LOOP('',(#1704,#1705,#1706,#1712));
#1714=FACE_BOUND('',#1713,.T.);
#1715=ADVANCED_FACE('F1101',(#1714),#1703,.F.);
#1716=CARTESIAN_POINT('',(-1.33669022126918E-13,87.6500000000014,0.));
#1717=DIRECTION('',(0.,1.,0.));
#1718=DIRECTION('',(-1.,0.,0.));
#1719=AXIS2_PLACEMENT_3D('',#1716,#1717,#1718);
#1720=PLANE('',#1719);
#1721=ORIENTED_EDGE('',*,*,#409,.T.);
#1722=ORIENTED_EDGE('',*,*,#1711,.F.);
#1723=ORIENTED_EDGE('',*,*,#1006,.F.);
#1724=DIRECTION('',(0.,0.,1.));
#1725=VECTOR('',#1724,1.);
#1726=CARTESIAN_POINT('',(112.1,87.6500000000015,0.));
#1727=LINE('',#1726,#1725);
#1728=EDGE_CURVE('E689',#997,#351,#1727,.T.);
#1729=ORIENTED_EDGE('',*,*,#1728,.T.);
#1730=EDGE_LOOP('',(#1721,#1722,#1723,#1729));
#1731=FACE_BOUND('',#1730,.T.);
#1732=ADVANCED_FACE('F1109',(#1731),#1720,.F.);
#1733=CARTESIAN_POINT('',(113.6,86.1500000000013,0.));
#1734=DIRECTION('',(0.,0.,1.));
#1735=DIRECTION('',(1.,0.,0.));
#1736=AXIS2_PLACEMENT_3D('',#1733,#1734,#1735);
#1737=CYLINDRICAL_SURFACE('',#1736,2.12132034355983);
#1738=ORIENTED_EDGE('',*,*,#352,.T.);
#1739=ORIENTED_EDGE('',*,*,#1728,.F.);
#1740=ORIENTED_EDGE('',*,*,#998,.F.);
#1741=ORIENTED_EDGE('',*,*,#1619,.T.);
#1742=EDGE_LOOP('',(#1738,#1739,#1740,#1741));
#1743=FACE_BOUND('',#1742,.T.);
#1744=ADVANCED_FACE('F1117',(#1743),#1737,.F.);
#1745=CARTESIAN_POINT('',(115.1,0.,0.));
#1746=DIRECTION('',(1.,0.,0.));
#1747=DIRECTION('',(0.,0.,-1.));
#1748=AXIS2_PLACEMENT_3D('',#1745,#1746,#1747);
#1749=PLANE('',#1748);
#1750=ORIENTED_EDGE('',*,*,#430,.T.);
#1751=DIRECTION('',(0.,0.,1.));
#1752=VECTOR('',#1751,1.);
#1753=CARTESIAN_POINT('',(115.1,54.5500000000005,0.));
#1754=LINE('',#1753,#1752);
#1755=EDGE_CURVE('E622',#1058,#419,#1754,.T.);
#1756=ORIENTED_EDGE('',*,*,#1755,.F.);
#1757=ORIENTED_EDGE('',*,*,#1059,.F.);
#1758=DIRECTION('',(0.,0.,1.));
#1759=VECTOR('',#1758,1.);
#1760=CARTESIAN_POINT('',(115.1,45.4500000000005,0.));
#1761=LINE('',#1760,#1759);
#1762=EDGE_CURVE('E600',#1056,#429,#1761,.T.);
#1763=ORIENTED_EDGE('',*,*,#1762,.T.);
#1764=EDGE_LOOP('',(#1750,#1756,#1757,#1763));
#1765=FACE_BOUND('',#1764,.T.);
#1766=ADVANCED_FACE('F1125',(#1765),#1749,.F.);
#1767=CARTESIAN_POINT('',(113.6,43.9500000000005,0.));
#1768=DIRECTION('',(0.,0.,1.));
#1769=DIRECTION('',(1.,0.,0.));
#1770=AXIS2_PLACEMENT_3D('',#1767,#1768,#1769);
#1771=CYLINDRICAL_SURFACE('',#1770,2.12132034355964);
#1772=ORIENTED_EDGE('',*,*,#439,.T.);
#1773=ORIENTED_EDGE('',*,*,#1762,.F.);
#1774=ORIENTED_EDGE('',*,*,#1117,.F.);
#1775=DIRECTION('',(0.,0.,1.));
#1776=VECTOR('',#1775,1.);
#1777=CARTESIAN_POINT('',(112.1,42.4500000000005,0.));
#1778=LINE('',#1777,#1776);
#1779=EDGE_CURVE('E636',#1109,#438,#1778,.T.);
#1780=ORIENTED_EDGE('',*,*,#1779,.T.);
#1781=EDGE_LOOP('',(#1772,#1773,#1774,#1780));
#1782=FACE_BOUND('',#1781,.T.);
#1783=ADVANCED_FACE('F1133',(#1782),#1771,.F.);
#1784=CARTESIAN_POINT('',(0.,42.4500000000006,0.));
#1785=DIRECTION('',(0.,-1.,0.));
#1786=DIRECTION('',(1.,0.,0.));
#1787=AXIS2_PLACEMENT_3D('',#1784,#1785,#1786);
#1788=PLANE('',#1787);
#1789=ORIENTED_EDGE('',*,*,#447,.T.);
#1790=ORIENTED_EDGE('',*,*,#1779,.F.);
#1791=ORIENTED_EDGE('',*,*,#1110,.F.);
#1792=DIRECTION('',(0.,0.,1.));
#1793=VECTOR('',#1792,1.);
#1794=CARTESIAN_POINT('',(103.,42.4500000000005,0.));
#1795=LINE('',#1794,#1793);
#1796=EDGE_CURVE('E634',#1101,#446,#1795,.T.);
#1797=ORIENTED_EDGE('',*,*,#1796,.T.);
#1798=EDGE_LOOP('',(#1789,#1790,#1791,#1797));
#1799=FACE_BOUND('',#1798,.T.);
#1800=ADVANCED_FACE('F1141',(#1799),#1788,.F.);
#1801=CARTESIAN_POINT('',(101.5,43.9500000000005,0.));
#1802=DIRECTION('',(0.,0.,1.));
#1803=DIRECTION('',(1.,0.,0.));
#1804=AXIS2_PLACEMENT_3D('',#1801,#1802,#1803);
#1805=CYLINDRICAL_SURFACE('',#1804,2.12132034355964);
#1806=ORIENTED_EDGE('',*,*,#456,.T.);
#1807=ORIENTED_EDGE('',*,*,#1796,.F.);
#1808=ORIENTED_EDGE('',*,*,#1102,.F.);
#1809=DIRECTION('',(0.,0.,1.));
#1810=VECTOR('',#1809,1.);
#1811=CARTESIAN_POINT('',(100.,45.4500000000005,0.));
#1812=LINE('',#1811,#1810);
#1813=EDGE_CURVE('E632',#1092,#455,#1812,.T.);
#1814=ORIENTED_EDGE('',*,*,#1813,.T.);
#1815=EDGE_LOOP('',(#1806,#1807,#1808,#1814));
#1816=FACE_BOUND('',#1815,.T.);
#1817=ADVANCED_FACE('F1149',(#1816),#1805,.F.);
#1818=CARTESIAN_POINT('',(100.,0.,0.));
#1819=DIRECTION('',(-1.,0.,0.));
#1820=DIRECTION('',(0.,0.,1.));
#1821=AXIS2_PLACEMENT_3D('',#1818,#1819,#1820);
#1822=PLANE('',#1821);
#1823=ORIENTED_EDGE('',*,*,#464,.T.);
#1824=ORIENTED_EDGE('',*,*,#1813,.F.);
#1825=ORIENTED_EDGE('',*,*,#1093,.F.);
#1826=DIRECTION('',(0.,0.,1.));
#1827=VECTOR('',#1826,1.);
#1828=CARTESIAN_POINT('',(100.,54.5500000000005,0.));
#1829=LINE('',#1828,#1827);
#1830=EDGE_CURVE('E630',#1084,#463,#1829,.T.);
#1831=ORIENTED_EDGE('',*,*,#1830,.T.);
#1832=EDGE_LOOP('',(#1823,#1824,#1825,#1831));
#1833=FACE_BOUND('',#1832,.T.);
#1834=ADVANCED_FACE('F1157',(#1833),#1822,.F.);
#1835=CARTESIAN_POINT('',(101.5,56.0500000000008,0.));
#1836=DIRECTION('',(0.,0.,1.));
#1837=DIRECTION('',(1.,0.,0.));
#1838=AXIS2_PLACEMENT_3D('',#1835,#1836,#1837);
#1839=CYLINDRICAL_SURFACE('',#1838,2.12132034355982);
#1840=ORIENTED_EDGE('',*,*,#473,.F.);
#1841=ORIENTED_EDGE('',*,*,#1830,.F.);
#1842=ORIENTED_EDGE('',*,*,#1085,.T.);
#1843=DIRECTION('',(0.,0.,1.));
#1844=VECTOR('',#1843,1.);
#1845=CARTESIAN_POINT('',(103.,57.550000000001,0.));
#1846=LINE('',#1845,#1844);
#1847=EDGE_CURVE('E628',#1075,#472,#1846,.T.);
#1848=ORIENTED_EDGE('',*,*,#1847,.T.);
#1849=EDGE_LOOP('',(#1840,#1841,#1842,#1848));
#1850=FACE_BOUND('',#1849,.T.);
#1851=ADVANCED_FACE('F1165',(#1850),#1839,.F.);
#1852=CARTESIAN_POINT('',(0.,57.5500000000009,0.));
#1853=DIRECTION('',(0.,1.,0.));
#1854=DIRECTION('',(-1.,0.,0.));
#1855=AXIS2_PLACEMENT_3D('',#1852,#1853,#1854);
#1856=PLANE('',#1855);
#1857=ORIENTED_EDGE('',*,*,#479,.T.);
#1858=ORIENTED_EDGE('',*,*,#1847,.F.);
#1859=ORIENTED_EDGE('',*,*,#1076,.F.);
#1860=DIRECTION('',(0.,0.,1.));
#1861=VECTOR('',#1860,1.);
#1862=CARTESIAN_POINT('',(112.1,57.550000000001,0.));
#1863=LINE('',#1862,#1861);
#1864=EDGE_CURVE('E626',#1067,#421,#1863,.T.);
#1865=ORIENTED_EDGE('',*,*,#1864,.T.);
#1866=EDGE_LOOP('',(#1857,#1858,#1859,#1865));
#1867=FACE_BOUND('',#1866,.T.);
#1868=ADVANCED_FACE('F1173',(#1867),#1856,.F.);
#1869=CARTESIAN_POINT('',(113.6,56.0500000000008,0.));
#1870=DIRECTION('',(0.,0.,1.));
#1871=DIRECTION('',(1.,0.,0.));
#1872=AXIS2_PLACEMENT_3D('',#1869,#1870,#1871);
#1873=CYLINDRICAL_SURFACE('',#1872,2.12132034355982);
#1874=ORIENTED_EDGE('',*,*,#422,.T.);
#1875=ORIENTED_EDGE('',*,*,#1864,.F.);
#1876=ORIENTED_EDGE('',*,*,#1068,.F.);
#1877=ORIENTED_EDGE('',*,*,#1755,.T.);
#1878=EDGE_LOOP('',(#1874,#1875,#1876,#1877));
#1879=FACE_BOUND('',#1878,.T.);
#1880=ADVANCED_FACE('F1181',(#1879),#1873,.F.);
#1881=CARTESIAN_POINT('',(115.1,0.,0.));
#1882=DIRECTION('',(1.,0.,0.));
#1883=DIRECTION('',(0.,0.,-1.));
#1884=AXIS2_PLACEMENT_3D('',#1881,#1882,#1883);
#1885=PLANE('',#1884);
#1886=ORIENTED_EDGE('',*,*,#500,.T.);
#1887=DIRECTION('',(0.,0.,1.));
#1888=VECTOR('',#1887,1.);
#1889=CARTESIAN_POINT('',(115.1,24.45,0.));
#1890=LINE('',#1889,#1888);
#1891=EDGE_CURVE('E559',#1128,#489,#1890,.T.);
#1892=ORIENTED_EDGE('',*,*,#1891,.F.);
#1893=ORIENTED_EDGE('',*,*,#1129,.F.);
#1894=DIRECTION('',(0.,0.,1.));
#1895=VECTOR('',#1894,1.);
#1896=CARTESIAN_POINT('',(115.1,15.35,0.));
#1897=LINE('',#1896,#1895);
#1898=EDGE_CURVE('E556',#1126,#499,#1897,.T.);
#1899=ORIENTED_EDGE('',*,*,#1898,.T.);
#1900=EDGE_LOOP('',(#1886,#1892,#1893,#1899));
#1901=FACE_BOUND('',#1900,.T.);
#1902=ADVANCED_FACE('F1189',(#1901),#1885,.F.);
#1903=CARTESIAN_POINT('',(113.6,13.85,0.));
#1904=DIRECTION('',(0.,0.,1.));
#1905=DIRECTION('',(1.,0.,0.));
#1906=AXIS2_PLACEMENT_3D('',#1903,#1904,#1905);
#1907=CYLINDRICAL_SURFACE('',#1906,2.12132034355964);
#1908=ORIENTED_EDGE('',*,*,#509,.T.);
#1909=ORIENTED_EDGE('',*,*,#1898,.F.);
#1910=ORIENTED_EDGE('',*,*,#1187,.F.);
#1911=DIRECTION('',(0.,0.,1.));
#1912=VECTOR('',#1911,1.);
#1913=CARTESIAN_POINT('',(112.1,12.35,0.));
#1914=LINE('',#1913,#1912);
#1915=EDGE_CURVE('E573',#1179,#508,#1914,.T.);
#1916=ORIENTED_EDGE('',*,*,#1915,.T.);
#1917=EDGE_LOOP('',(#1908,#1909,#1910,#1916));
#1918=FACE_BOUND('',#1917,.T.);
#1919=ADVANCED_FACE('F1197',(#1918),#1907,.F.);
#1920=CARTESIAN_POINT('',(0.,12.35,0.));
#1921=DIRECTION('',(0.,-1.,0.));
#1922=DIRECTION('',(0.,0.,-1.));
#1923=AXIS2_PLACEMENT_3D('',#1920,#1921,#1922);
#1924=PLANE('',#1923);
#1925=ORIENTED_EDGE('',*,*,#517,.T.);
#1926=ORIENTED_EDGE('',*,*,#1915,.F.);
#1927=ORIENTED_EDGE('',*,*,#1180,.F.);
#1928=DIRECTION('',(0.,0.,1.));
#1929=VECTOR('',#1928,1.);
#1930=CARTESIAN_POINT('',(103.,12.35,0.));
#1931=LINE('',#1930,#1929);
#1932=EDGE_CURVE('E571',#1171,#516,#1931,.T.);
#1933=ORIENTED_EDGE('',*,*,#1932,.T.);
#1934=EDGE_LOOP('',(#1925,#1926,#1927,#1933));
#1935=FACE_BOUND('',#1934,.T.);
#1936=ADVANCED_FACE('F1205',(#1935),#1924,.F.);
#1937=CARTESIAN_POINT('',(101.5,13.85,0.));
#1938=DIRECTION('',(0.,0.,1.));
#1939=DIRECTION('',(1.,0.,0.));
#1940=AXIS2_PLACEMENT_3D('',#1937,#1938,#1939);
#1941=CYLINDRICAL_SURFACE('',#1940,2.12132034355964);
#1942=ORIENTED_EDGE('',*,*,#526,.T.);
#1943=ORIENTED_EDGE('',*,*,#1932,.F.);
#1944=ORIENTED_EDGE('',*,*,#1172,.F.);
#1945=DIRECTION('',(0.,0.,1.));
#1946=VECTOR('',#1945,1.);
#1947=CARTESIAN_POINT('',(100.,15.35,0.));
#1948=LINE('',#1947,#1946);
#1949=EDGE_CURVE('E569',#1162,#525,#1948,.T.);
#1950=ORIENTED_EDGE('',*,*,#1949,.T.);
#1951=EDGE_LOOP('',(#1942,#1943,#1944,#1950));
#1952=FACE_BOUND('',#1951,.T.);
#1953=ADVANCED_FACE('F1213',(#1952),#1941,.F.);
#1954=CARTESIAN_POINT('',(100.,0.,0.));
#1955=DIRECTION('',(-1.,0.,0.));
#1956=DIRECTION('',(0.,0.,1.));
#1957=AXIS2_PLACEMENT_3D('',#1954,#1955,#1956);
#1958=PLANE('',#1957);
#1959=ORIENTED_EDGE('',*,*,#534,.T.);
#1960=ORIENTED_EDGE('',*,*,#1949,.F.);
#1961=ORIENTED_EDGE('',*,*,#1163,.F.);
#1962=DIRECTION('',(0.,0.,1.));
#1963=VECTOR('',#1962,1.);
#1964=CARTESIAN_POINT('',(100.,24.45,0.));
#1965=LINE('',#1964,#1963);
#1966=EDGE_CURVE('E567',#1154,#533,#1965,.T.);
#1967=ORIENTED_EDGE('',*,*,#1966,.T.);
#1968=EDGE_LOOP('',(#1959,#1960,#1961,#1967));
#1969=FACE_BOUND('',#1968,.T.);
#1970=ADVANCED_FACE('F1221',(#1969),#1958,.F.);
#1971=CARTESIAN_POINT('',(101.5,25.9500000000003,0.));
#1972=DIRECTION('',(0.,0.,1.));
#1973=DIRECTION('',(1.,0.,0.));
#1974=AXIS2_PLACEMENT_3D('',#1971,#1972,#1973);
#1975=CYLINDRICAL_SURFACE('',#1974,2.12132034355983);
#1976=ORIENTED_EDGE('',*,*,#543,.F.);
#1977=ORIENTED_EDGE('',*,*,#1966,.F.);
#1978=ORIENTED_EDGE('',*,*,#1155,.T.);
#1979=DIRECTION('',(0.,0.,1.));
#1980=VECTOR('',#1979,1.);
#1981=CARTESIAN_POINT('',(103.,27.4500000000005,0.));
#1982=LINE('',#1981,#1980);
#1983=EDGE_CURVE('E565',#1145,#542,#1982,.T.);
#1984=ORIENTED_EDGE('',*,*,#1983,.T.);
#1985=EDGE_LOOP('',(#1976,#1977,#1978,#1984));
#1986=FACE_BOUND('',#1985,.T.);
#1987=ADVANCED_FACE('F1229',(#1986),#1975,.F.);
#1988=CARTESIAN_POINT('',(0.,27.4500000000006,0.));
#1989=DIRECTION('',(0.,1.,0.));
#1990=DIRECTION('',(-1.,0.,0.));
#1991=AXIS2_PLACEMENT_3D('',#1988,#1989,#1990);
#1992=PLANE('',#1991);
#1993=ORIENTED_EDGE('',*,*,#549,.T.);
#1994=ORIENTED_EDGE('',*,*,#1983,.F.);
#1995=ORIENTED_EDGE('',*,*,#1146,.F.);
#1996=DIRECTION('',(0.,0.,1.));
#1997=VECTOR('',#1996,1.);
#1998=CARTESIAN_POINT('',(112.1,27.4500000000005,0.));
#1999=LINE('',#1998,#1997);
#2000=EDGE_CURVE('E563',#1137,#491,#1999,.T.);
#2001=ORIENTED_EDGE('',*,*,#2000,.T.);
#2002=EDGE_LOOP('',(#1993,#1994,#1995,#2001));
#2003=FACE_BOUND('',#2002,.T.);
#2004=ADVANCED_FACE('F1237',(#2003),#1992,.F.);
#2005=CARTESIAN_POINT('',(113.6,25.9500000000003,0.));
#2006=DIRECTION('',(0.,0.,1.));
#2007=DIRECTION('',(1.,0.,0.));
#2008=AXIS2_PLACEMENT_3D('',#2005,#2006,#2007);
#2009=CYLINDRICAL_SURFACE('',#2008,2.12132034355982);
#2010=ORIENTED_EDGE('',*,*,#492,.T.);
#2011=ORIENTED_EDGE('',*,*,#2000,.F.);
#2012=ORIENTED_EDGE('',*,*,#1138,.F.);
#2013=ORIENTED_EDGE('',*,*,#1891,.T.);
#2014=EDGE_LOOP('',(#2010,#2011,#2012,#2013));
#2015=FACE_BOUND('',#2014,.T.);
#2016=ADVANCED_FACE('F1245',(#2015),#2009,.F.);
#2017=CARTESIAN_POINT('',(45.5,69.5,0.));
#2018=DIRECTION('',(0.,0.,1.));
#2019=DIRECTION('',(1.,0.,0.));
#2020=AXIS2_PLACEMENT_3D('',#2017,#2018,#2019);
#2021=CYLINDRICAL_SURFACE('',#2020,12.);
#2022=ORIENTED_EDGE('',*,*,#1198,.F.);
#2023=EDGE_LOOP('',(#2022));
#2024=FACE_BOUND('',#2023,.T.);
#2025=ORIENTED_EDGE('',*,*,#560,.T.);
#2026=EDGE_LOOP('',(#2025));
#2027=FACE_BOUND('',#2026,.T.);
#2028=ADVANCED_FACE('F1253',(#2024,#2027),#2021,.F.);
#2029=CARTESIAN_POINT('',(30.,54.,0.));
#2030=DIRECTION('',(0.,0.,1.));
#2031=DIRECTION('',(1.,0.,0.));
#2032=AXIS2_PLACEMENT_3D('',#2029,#2030,#2031);
#2033=CYLINDRICAL_SURFACE('',#2032,3.);
#2034=ORIENTED_EDGE('',*,*,#1209,.F.);
#2035=EDGE_LOOP('',(#2034));
#2036=FACE_BOUND('',#2035,.T.);
#2037=ORIENTED_EDGE('',*,*,#571,.T.);
#2038=EDGE_LOOP('',(#2037));
#2039=FACE_BOUND('',#2038,.T.);
#2040=ADVANCED_FACE('F1261',(#2036,#2039),#2033,.F.);
#2041=CARTESIAN_POINT('',(30.,85.,0.));
#2042=DIRECTION('',(0.,0.,1.));
#2043=DIRECTION('',(1.,0.,0.));
#2044=AXIS2_PLACEMENT_3D('',#2041,#2042,#2043);
#2045=CYLINDRICAL_SURFACE('',#2044,3.);
#2046=ORIENTED_EDGE('',*,*,#1220,.F.);
#2047=EDGE_LOOP('',(#2046));
#2048=FACE_BOUND('',#2047,.T.);
#2049=ORIENTED_EDGE('',*,*,#582,.T.);
#2050=EDGE_LOOP('',(#2049));
#2051=FACE_BOUND('',#2050,.T.);
#2052=ADVANCED_FACE('F1269',(#2048,#2051),#2045,.F.);
#2053=CARTESIAN_POINT('',(61.,85.,0.));
#2054=DIRECTION('',(0.,0.,1.));
#2055=DIRECTION('',(1.,0.,0.));
#2056=AXIS2_PLACEMENT_3D('',#2053,#2054,#2055);
#2057=CYLINDRICAL_SURFACE('',#2056,3.00000000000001);
#2058=ORIENTED_EDGE('',*,*,#1231,.F.);
#2059=EDGE_LOOP('',(#2058));
#2060=FACE_BOUND('',#2059,.T.);
#2061=ORIENTED_EDGE('',*,*,#593,.T.);
#2062=EDGE_LOOP('',(#2061));
#2063=FACE_BOUND('',#2062,.T.);
#2064=ADVANCED_FACE('F1277',(#2060,#2063),#2057,.F.);
#2065=CARTESIAN_POINT('',(61.,54.,0.));
#2066=DIRECTION('',(0.,0.,1.));
#2067=DIRECTION('',(1.,0.,0.));
#2068=AXIS2_PLACEMENT_3D('',#2065,#2066,#2067);
#2069=CYLINDRICAL_SURFACE('',#2068,3.00000000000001);
#2070=ORIENTED_EDGE('',*,*,#1242,.F.);
#2071=EDGE_LOOP('',(#2070));
#2072=FACE_BOUND('',#2071,.T.);
#2073=ORIENTED_EDGE('',*,*,#604,.T.);
#2074=EDGE_LOOP('',(#2073));
#2075=FACE_BOUND('',#2074,.T.);
#2076=ADVANCED_FACE('F1285',(#2072,#2075),#2069,.F.);
#2077=CARTESIAN_POINT('',(486.4,56.0500000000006,0.));
#2078=DIRECTION('',(0.,0.,1.));
#2079=DIRECTION('',(1.,0.,0.));
#2080=AXIS2_PLACEMENT_3D('',#2077,#2078,#2079);
#2081=CYLINDRICAL_SURFACE('',#2080,2.12132034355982);
#2082=ORIENTED_EDGE('',*,*,#617,.F.);
#2083=DIRECTION('',(0.,0.,1.));
#2084=VECTOR('',#2083,1.);
#2085=CARTESIAN_POINT('',(484.9,54.5500000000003,0.));
#2086=LINE('',#2085,#2084);
#2087=EDGE_CURVE('E478',#1262,#614,#2086,.T.);
#2088=ORIENTED_EDGE('',*,*,#2087,.F.);
#2089=ORIENTED_EDGE('',*,*,#1263,.T.);
#2090=DIRECTION('',(0.,0.,1.));
#2091=VECTOR('',#2090,1.);
#2092=CARTESIAN_POINT('',(487.9,57.5500000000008,0.));
#2093=LINE('',#2092,#2091);
#2094=EDGE_CURVE('E437',#1253,#616,#2093,.T.);
#2095=ORIENTED_EDGE('',*,*,#2094,.T.);
#2096=EDGE_LOOP('',(#2082,#2088,#2089,#2095));
#2097=FACE_BOUND('',#2096,.T.);
#2098=ADVANCED_FACE('F1293',(#2097),#2081,.F.);
#2099=CARTESIAN_POINT('',(497.,57.5500000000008,0.));
#2100=DIRECTION('',(0.,1.,0.));
#2101=DIRECTION('',(0.,0.,1.));
#2102=AXIS2_PLACEMENT_3D('',#2099,#2100,#2101);
#2103=PLANE('',#2102);
#2104=ORIENTED_EDGE('',*,*,#625,.T.);
#2105=ORIENTED_EDGE('',*,*,#2094,.F.);
#2106=ORIENTED_EDGE('',*,*,#1254,.F.);
#2107=DIRECTION('',(0.,0.,1.));
#2108=VECTOR('',#2107,1.);
#2109=CARTESIAN_POINT('',(497.,57.5500000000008,0.));
#2110=LINE('',#2109,#2108);
#2111=EDGE_CURVE('E439',#1251,#624,#2110,.T.);
#2112=ORIENTED_EDGE('',*,*,#2111,.T.);
#2113=EDGE_LOOP('',(#2104,#2105,#2106,#2112));
#2114=FACE_BOUND('',#2113,.T.);
#2115=ADVANCED_FACE('F1301',(#2114),#2103,.F.);
#2116=CARTESIAN_POINT('',(498.5,56.0500000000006,0.));
#2117=DIRECTION('',(0.,0.,1.));
#2118=DIRECTION('',(1.,0.,0.));
#2119=AXIS2_PLACEMENT_3D('',#2116,#2117,#2118);
#2120=CYLINDRICAL_SURFACE('',#2119,2.12132034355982);
#2121=ORIENTED_EDGE('',*,*,#634,.T.);
#2122=ORIENTED_EDGE('',*,*,#2111,.F.);
#2123=ORIENTED_EDGE('',*,*,#1312,.F.);
#2124=DIRECTION('',(0.,0.,1.));
#2125=VECTOR('',#2124,1.);
#2126=CARTESIAN_POINT('',(500.,54.5500000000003,0.));
#2127=LINE('',#2126,#2125);
#2128=EDGE_CURVE('E468',#1304,#633,#2127,.T.);
#2129=ORIENTED_EDGE('',*,*,#2128,.T.);
#2130=EDGE_LOOP('',(#2121,#2122,#2123,#2129));
#2131=FACE_BOUND('',#2130,.T.);
#2132=ADVANCED_FACE('F1309',(#2131),#2120,.F.);
#2133=CARTESIAN_POINT('',(500.,45.4500000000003,0.));
#2134=DIRECTION('',(1.,0.,0.));
#2135=DIRECTION('',(0.,0.,-1.));
#2136=AXIS2_PLACEMENT_3D('',#2133,#2134,#2135);
#2137=PLANE('',#2136);
#2138=ORIENTED_EDGE('',*,*,#642,.T.);
#2139=ORIENTED_EDGE('',*,*,#2128,.F.);
#2140=ORIENTED_EDGE('',*,*,#1305,.F.);
#2141=DIRECTION('',(0.,0.,1.));
#2142=VECTOR('',#2141,1.);
#2143=CARTESIAN_POINT('',(500.,45.4500000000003,0.));
#2144=LINE('',#2143,#2142);
#2145=EDGE_CURVE('E470',#1296,#641,#2144,.T.);
#2146=ORIENTED_EDGE('',*,*,#2145,.T.);
#2147=EDGE_LOOP('',(#2138,#2139,#2140,#2146));
#2148=FACE_BOUND('',#2147,.T.);
#2149=ADVANCED_FACE('F1317',(#2148),#2137,.F.);
#2150=CARTESIAN_POINT('',(498.5,43.9500000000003,0.));
#2151=DIRECTION('',(0.,0.,1.));
#2152=DIRECTION('',(1.,0.,0.));
#2153=AXIS2_PLACEMENT_3D('',#2150,#2151,#2152);
#2154=CYLINDRICAL_SURFACE('',#2153,2.12132034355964);
#2155=ORIENTED_EDGE('',*,*,#651,.T.);
#2156=ORIENTED_EDGE('',*,*,#2145,.F.);
#2157=ORIENTED_EDGE('',*,*,#1297,.F.);
#2158=DIRECTION('',(0.,0.,1.));
#2159=VECTOR('',#2158,1.);
#2160=CARTESIAN_POINT('',(497.,42.4500000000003,0.));
#2161=LINE('',#2160,#2159);
#2162=EDGE_CURVE('E472',#1287,#650,#2161,.T.);
#2163=ORIENTED_EDGE('',*,*,#2162,.T.);
#2164=EDGE_LOOP('',(#2155,#2156,#2157,#2163));
#2165=FACE_BOUND('',#2164,.T.);
#2166=ADVANCED_FACE('F1325',(#2165),#2154,.F.);
#2167=CARTESIAN_POINT('',(487.9,42.4500000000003,0.));
#2168=DIRECTION('',(0.,-1.,0.));
#2169=DIRECTION('',(0.,0.,-1.));
#2170=AXIS2_PLACEMENT_3D('',#2167,#2168,#2169);
#2171=PLANE('',#2170);
#2172=ORIENTED_EDGE('',*,*,#659,.T.);
#2173=ORIENTED_EDGE('',*,*,#2162,.F.);
#2174=ORIENTED_EDGE('',*,*,#1288,.F.);
#2175=DIRECTION('',(0.,0.,1.));
#2176=VECTOR('',#2175,1.);
#2177=CARTESIAN_POINT('',(487.9,42.4500000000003,0.));
#2178=LINE('',#2177,#2176);
#2179=EDGE_CURVE('E474',#1279,#658,#2178,.T.);
#2180=ORIENTED_EDGE('',*,*,#2179,.T.);
#2181=EDGE_LOOP('',(#2172,#2173,#2174,#2180));
#2182=FACE_BOUND('',#2181,.T.);
#2183=ADVANCED_FACE('F1333',(#2182),#2171,.F.);
#2184=CARTESIAN_POINT('',(486.4,43.9500000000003,0.));
#2185=DIRECTION('',(0.,0.,1.));
#2186=DIRECTION('',(1.,0.,0.));
#2187=AXIS2_PLACEMENT_3D('',#2184,#2185,#2186);
#2188=CYLINDRICAL_SURFACE('',#2187,2.12132034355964);
#2189=ORIENTED_EDGE('',*,*,#668,.T.);
#2190=ORIENTED_EDGE('',*,*,#2179,.F.);
#2191=ORIENTED_EDGE('',*,*,#1280,.F.);
#2192=DIRECTION('',(0.,0.,1.));
#2193=VECTOR('',#2192,1.);
#2194=CARTESIAN_POINT('',(484.9,45.4500000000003,0.));
#2195=LINE('',#2194,#2193);
#2196=EDGE_CURVE('E476',#1270,#667,#2195,.T.);
#2197=ORIENTED_EDGE('',*,*,#2196,.T.);
#2198=EDGE_LOOP('',(#2189,#2190,#2191,#2197));
#2199=FACE_BOUND('',#2198,.T.);
#2200=ADVANCED_FACE('F1341',(#2199),#2188,.F.);
#2201=CARTESIAN_POINT('',(484.9,54.5500000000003,0.));
#2202=DIRECTION('',(-1.,0.,0.));
#2203=DIRECTION('',(0.,0.,1.));
#2204=AXIS2_PLACEMENT_3D('',#2201,#2202,#2203);
#2205=PLANE('',#2204);
#2206=ORIENTED_EDGE('',*,*,#674,.T.);
#2207=ORIENTED_EDGE('',*,*,#2196,.F.);
#2208=ORIENTED_EDGE('',*,*,#1271,.F.);
#2209=ORIENTED_EDGE('',*,*,#2087,.T.);
#2210=EDGE_LOOP('',(#2206,#2207,#2208,#2209));
#2211=FACE_BOUND('',#2210,.T.);
#2212=ADVANCED_FACE('F1349',(#2211),#2205,.F.);
#2213=CARTESIAN_POINT('',(498.5,25.9500000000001,0.));
#2214=DIRECTION('',(0.,0.,1.));
#2215=DIRECTION('',(1.,0.,0.));
#2216=AXIS2_PLACEMENT_3D('',#2213,#2214,#2215);
#2217=CYLINDRICAL_SURFACE('',#2216,2.12132034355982);
#2218=ORIENTED_EDGE('',*,*,#118,.T.);
#2219=DIRECTION('',(0.,0.,1.));
#2220=VECTOR('',#2219,1.);
#2221=CARTESIAN_POINT('',(497.,27.4500000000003,0.));
#2222=LINE('',#2221,#2220);
#2223=EDGE_CURVE('E448',#747,#106,#2222,.T.);
#2224=ORIENTED_EDGE('',*,*,#2223,.F.);
#2225=ORIENTED_EDGE('',*,*,#748,.F.);
#2226=DIRECTION('',(0.,0.,1.));
#2227=VECTOR('',#2226,1.);
#2228=CARTESIAN_POINT('',(500.,24.4499999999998,0.));
#2229=LINE('',#2228,#2227);
#2230=EDGE_CURVE('E411',#745,#117,#2229,.T.);
#2231=ORIENTED_EDGE('',*,*,#2230,.T.);
#2232=EDGE_LOOP('',(#2218,#2224,#2225,#2231));
#2233=FACE_BOUND('',#2232,.T.);
#2234=ADVANCED_FACE('F413',(#2233),#2217,.F.);
#2235=CARTESIAN_POINT('',(500.,15.3499999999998,0.));
#2236=DIRECTION('',(1.,0.,0.));
#2237=DIRECTION('',(0.,0.,-1.));
#2238=AXIS2_PLACEMENT_3D('',#2235,#2236,#2237);
#2239=PLANE('',#2238);
#2240=ORIENTED_EDGE('',*,*,#126,.T.);
#2241=ORIENTED_EDGE('',*,*,#2230,.F.);
#2242=ORIENTED_EDGE('',*,*,#805,.F.);
#2243=DIRECTION('',(0.,0.,1.));
#2244=VECTOR('',#2243,1.);
#2245=CARTESIAN_POINT('',(500.,15.3499999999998,0.));
#2246=LINE('',#2245,#2244);
#2247=EDGE_CURVE('E422',#798,#125,#2246,.T.);
#2248=ORIENTED_EDGE('',*,*,#2247,.T.);
#2249=EDGE_LOOP('',(#2240,#2241,#2242,#2248));
#2250=FACE_BOUND('',#2249,.T.);
#2251=ADVANCED_FACE('F427',(#2250),#2239,.F.);
#2252=CARTESIAN_POINT('',(498.5,13.8499999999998,0.));
#2253=DIRECTION('',(0.,0.,1.));
#2254=DIRECTION('',(1.,0.,0.));
#2255=AXIS2_PLACEMENT_3D('',#2252,#2253,#2254);
#2256=CYLINDRICAL_SURFACE('',#2255,2.12132034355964);
#2257=ORIENTED_EDGE('',*,*,#135,.T.);
#2258=ORIENTED_EDGE('',*,*,#2247,.F.);
#2259=ORIENTED_EDGE('',*,*,#799,.F.);
#2260=DIRECTION('',(0.,0.,1.));
#2261=VECTOR('',#2260,1.);
#2262=CARTESIAN_POINT('',(497.,12.3499999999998,0.));
#2263=LINE('',#2262,#2261);
#2264=EDGE_CURVE('E1732',#789,#134,#2263,.T.);
#2265=ORIENTED_EDGE('',*,*,#2264,.T.);
#2266=EDGE_LOOP('',(#2257,#2258,#2259,#2265));
#2267=FACE_BOUND('',#2266,.T.);
#2268=ADVANCED_FACE('F1370',(#2267),#2256,.F.);
#2269=CARTESIAN_POINT('',(487.9,12.3499999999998,0.));
#2270=DIRECTION('',(0.,-1.,0.));
#2271=DIRECTION('',(1.,0.,0.));
#2272=AXIS2_PLACEMENT_3D('',#2269,#2270,#2271);
#2273=PLANE('',#2272);
#2274=ORIENTED_EDGE('',*,*,#143,.T.);
#2275=ORIENTED_EDGE('',*,*,#2264,.F.);
#2276=ORIENTED_EDGE('',*,*,#790,.F.);
#2277=DIRECTION('',(0.,0.,1.));
#2278=VECTOR('',#2277,1.);
#2279=CARTESIAN_POINT('',(487.9,12.3499999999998,0.));
#2280=LINE('',#2279,#2278);
#2281=EDGE_CURVE('E1730',#781,#142,#2280,.T.);
#2282=ORIENTED_EDGE('',*,*,#2281,.T.);
#2283=EDGE_LOOP('',(#2274,#2275,#2276,#2282));
#2284=FACE_BOUND('',#2283,.T.);
#2285=ADVANCED_FACE('F1377',(#2284),#2273,.F.);
#2286=CARTESIAN_POINT('',(486.4,13.8499999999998,0.));
#2287=DIRECTION('',(0.,0.,1.));
#2288=DIRECTION('',(1.,0.,0.));
#2289=AXIS2_PLACEMENT_3D('',#2286,#2287,#2288);
#2290=CYLINDRICAL_SURFACE('',#2289,2.12132034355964);
#2291=ORIENTED_EDGE('',*,*,#152,.T.);
#2292=ORIENTED_EDGE('',*,*,#2281,.F.);
#2293=ORIENTED_EDGE('',*,*,#782,.F.);
#2294=DIRECTION('',(0.,0.,1.));
#2295=VECTOR('',#2294,1.);
#2296=CARTESIAN_POINT('',(484.9,15.3499999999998,0.));
#2297=LINE('',#2296,#2295);
#2298=EDGE_CURVE('E1728',#772,#151,#2297,.T.);
#2299=ORIENTED_EDGE('',*,*,#2298,.T.);
#2300=EDGE_LOOP('',(#2291,#2292,#2293,#2299));
#2301=FACE_BOUND('',#2300,.T.);
#2302=ADVANCED_FACE('F1385',(#2301),#2290,.F.);
#2303=CARTESIAN_POINT('',(484.9,24.4499999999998,0.));
#2304=DIRECTION('',(-1.,0.,0.));
#2305=DIRECTION('',(0.,0.,1.));
#2306=AXIS2_PLACEMENT_3D('',#2303,#2304,#2305);
#2307=PLANE('',#2306);
#2308=ORIENTED_EDGE('',*,*,#160,.T.);
#2309=ORIENTED_EDGE('',*,*,#2298,.F.);
#2310=ORIENTED_EDGE('',*,*,#773,.F.);
#2311=DIRECTION('',(0.,0.,1.));
#2312=VECTOR('',#2311,1.);
#2313=CARTESIAN_POINT('',(484.9,24.4499999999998,0.));
#2314=LINE('',#2313,#2312);
#2315=EDGE_CURVE('E1726',#764,#159,#2314,.T.);
#2316=ORIENTED_EDGE('',*,*,#2315,.T.);
#2317=EDGE_LOOP('',(#2308,#2309,#2310,#2316));
#2318=FACE_BOUND('',#2317,.T.);
#2319=ADVANCED_FACE('F1393',(#2318),#2307,.F.);
#2320=CARTESIAN_POINT('',(486.4,25.9500000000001,0.));
#2321=DIRECTION('',(0.,0.,1.));
#2322=DIRECTION('',(1.,0.,0.));
#2323=AXIS2_PLACEMENT_3D('',#2320,#2321,#2322);
#2324=CYLINDRICAL_SURFACE('',#2323,2.12132034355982);
#2325=ORIENTED_EDGE('',*,*,#167,.F.);
#2326=ORIENTED_EDGE('',*,*,#2315,.F.);
#2327=ORIENTED_EDGE('',*,*,#765,.T.);
#2328=DIRECTION('',(0.,0.,1.));
#2329=VECTOR('',#2328,1.);
#2330=CARTESIAN_POINT('',(487.9,27.4500000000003,0.));
#2331=LINE('',#2330,#2329);
#2332=EDGE_CURVE('E1724',#755,#108,#2331,.T.);
#2333=ORIENTED_EDGE('',*,*,#2332,.T.);
#2334=EDGE_LOOP('',(#2325,#2326,#2327,#2333));
#2335=FACE_BOUND('',#2334,.T.);
#2336=ADVANCED_FACE('F1401',(#2335),#2324,.F.);
#2337=CARTESIAN_POINT('',(497.,27.4500000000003,0.));
#2338=DIRECTION('',(0.,1.,0.));
#2339=DIRECTION('',(0.,0.,1.));
#2340=AXIS2_PLACEMENT_3D('',#2337,#2338,#2339);
#2341=PLANE('',#2340);
#2342=ORIENTED_EDGE('',*,*,#109,.T.);
#2343=ORIENTED_EDGE('',*,*,#2332,.F.);
#2344=ORIENTED_EDGE('',*,*,#756,.F.);
#2345=ORIENTED_EDGE('',*,*,#2223,.T.);
#2346=EDGE_LOOP('',(#2342,#2343,#2344,#2345));
#2347=FACE_BOUND('',#2346,.T.);
#2348=ADVANCED_FACE('F1409',(#2347),#2341,.F.);
#2349=CARTESIAN_POINT('',(539.,54.,0.));
#2350=DIRECTION('',(0.,0.,1.));
#2351=DIRECTION('',(1.,0.,0.));
#2352=AXIS2_PLACEMENT_3D('',#2349,#2350,#2351);
#2353=CYLINDRICAL_SURFACE('',#2352,3.00000000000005);
#2354=ORIENTED_EDGE('',*,*,#735,.F.);
#2355=EDGE_LOOP('',(#2354));
#2356=FACE_BOUND('',#2355,.T.);
#2357=ORIENTED_EDGE('',*,*,#97,.T.);
#2358=EDGE_LOOP('',(#2357));
#2359=FACE_BOUND('',#2358,.T.);
#2360=ADVANCED_FACE('F1417',(#2356,#2359),#2353,.F.);
#2361=CARTESIAN_POINT('',(554.5,69.5,0.));
#2362=DIRECTION('',(0.,0.,1.));
#2363=DIRECTION('',(1.,0.,0.));
#2364=AXIS2_PLACEMENT_3D('',#2361,#2362,#2363);
#2365=CYLINDRICAL_SURFACE('',#2364,12.);
#2366=ORIENTED_EDGE('',*,*,#724,.F.);
#2367=EDGE_LOOP('',(#2366));
#2368=FACE_BOUND('',#2367,.T.);
#2369=ORIENTED_EDGE('',*,*,#86,.T.);
#2370=EDGE_LOOP('',(#2369));
#2371=FACE_BOUND('',#2370,.T.);
#2372=ADVANCED_FACE('F1425',(#2368,#2371),#2365,.F.);
#2373=CARTESIAN_POINT('',(570.,54.,0.));
#2374=DIRECTION('',(0.,0.,1.));
#2375=DIRECTION('',(1.,0.,0.));
#2376=AXIS2_PLACEMENT_3D('',#2373,#2374,#2375);
#2377=CYLINDRICAL_SURFACE('',#2376,3.00000000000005);
#2378=ORIENTED_EDGE('',*,*,#713,.F.);
#2379=EDGE_LOOP('',(#2378));
#2380=FACE_BOUND('',#2379,.T.);
#2381=ORIENTED_EDGE('',*,*,#75,.T.);
#2382=EDGE_LOOP('',(#2381));
#2383=FACE_BOUND('',#2382,.T.);
#2384=ADVANCED_FACE('F1433',(#2380,#2383),#2377,.F.);
#2385=CARTESIAN_POINT('',(570.,85.,0.));
#2386=DIRECTION('',(0.,0.,1.));
#2387=DIRECTION('',(1.,0.,0.));
#2388=AXIS2_PLACEMENT_3D('',#2385,#2386,#2387);
#2389=CYLINDRICAL_SURFACE('',#2388,3.00000000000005);
#2390=ORIENTED_EDGE('',*,*,#702,.F.);
#2391=EDGE_LOOP('',(#2390));
#2392=FACE_BOUND('',#2391,.T.);
#2393=ORIENTED_EDGE('',*,*,#64,.T.);
#2394=EDGE_LOOP('',(#2393));
#2395=FACE_BOUND('',#2394,.T.);
#2396=ADVANCED_FACE('F1441',(#2392,#2395),#2389,.F.);
#2397=CARTESIAN_POINT('',(539.,85.,0.));
#2398=DIRECTION('',(0.,0.,1.));
#2399=DIRECTION('',(1.,0.,0.));
#2400=AXIS2_PLACEMENT_3D('',#2397,#2398,#2399);
#2401=CYLINDRICAL_SURFACE('',#2400,3.00000000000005);
#2402=ORIENTED_EDGE('',*,*,#691,.F.);
#2403=EDGE_LOOP('',(#2402));
#2404=FACE_BOUND('',#2403,.T.);
#2405=ORIENTED_EDGE('',*,*,#53,.T.);
#2406=EDGE_LOOP('',(#2405));
#2407=FACE_BOUND('',#2406,.T.);
#2408=ADVANCED_FACE('F1449',(#2404,#2407),#2401,.F.);
#2409=CARTESIAN_POINT('',(554.5,25.,7.5));
#2410=DIRECTION('',(0.,0.,1.));
#2411=DIRECTION('',(1.,0.,0.));
#2412=AXIS2_PLACEMENT_3D('',#2409,#2410,#2411);
#2413=CYLINDRICAL_SURFACE('',#2412,5.025);
#2414=CARTESIAN_POINT('',(554.5,25.,7.5));
#2415=DIRECTION('',(0.,0.,1.));
#2416=DIRECTION('',(1.,0.,0.));
#2417=AXIS2_PLACEMENT_3D('',#2414,#2415,#2416);
#2418=CIRCLE('',#2417,5.025);
#2419=CARTESIAN_POINT('',(559.525,25.,7.5));
#2420=VERTEX_POINT('',#2419);
#2421=EDGE_CURVE('E1681',#2420,#2420,#2418,.T.);
#2422=ORIENTED_EDGE('',*,*,#2421,.F.);
#2423=EDGE_LOOP('',(#2422));
#2424=FACE_BOUND('',#2423,.T.);
#2425=ORIENTED_EDGE('',*,*,#42,.T.);
#2426=EDGE_LOOP('',(#2425));
#2427=FACE_BOUND('',#2426,.T.);
#2428=ADVANCED_FACE('F1457',(#2424,#2427),#2413,.F.);
#2429=CARTESIAN_POINT('',(554.5,25.,7.5));
#2430=DIRECTION('',(0.,0.,1.));
#2431=DIRECTION('',(1.,0.,0.));
#2432=AXIS2_PLACEMENT_3D('',#2429,#2430,#2431);
#2433=PLANE('',#2432);
#2434=ORIENTED_EDGE('',*,*,#2421,.T.);
#2435=EDGE_LOOP('',(#2434));
#2436=FACE_BOUND('',#2435,.T.);
#2437=ADVANCED_FACE('F1465',(#2436),#2433,.T.);
#2438=CARTESIAN_POINT('',(45.5,25.,7.5));
#2439=DIRECTION('',(0.,0.,1.));
#2440=DIRECTION('',(1.,0.,0.));
#2441=AXIS2_PLACEMENT_3D('',#2438,#2439,#2440);
#2442=CYLINDRICAL_SURFACE('',#2441,5.025);
#2443=CARTESIAN_POINT('',(45.5,25.,7.5));
#2444=DIRECTION('',(0.,0.,1.));
#2445=DIRECTION('',(1.,0.,0.));
#2446=AXIS2_PLACEMENT_3D('',#2443,#2444,#2445);
#2447=CIRCLE('',#2446,5.025);
#2448=CARTESIAN_POINT('',(50.5249999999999,25.,7.5));
#2449=VERTEX_POINT('',#2448);
#2450=EDGE_CURVE('E1676',#2449,#2449,#2447,.T.);
#2451=ORIENTED_EDGE('',*,*,#2450,.F.);
#2452=EDGE_LOOP('',(#2451));
#2453=FACE_BOUND('',#2452,.T.);
#2454=ORIENTED_EDGE('',*,*,#31,.T.);
#2455=EDGE_LOOP('',(#2454));
#2456=FACE_BOUND('',#2455,.T.);
#2457=ADVANCED_FACE('F1473',(#2453,#2456),#2442,.F.);
#2458=CARTESIAN_POINT('',(45.5,25.,7.5));
#2459=DIRECTION('',(0.,0.,1.));
#2460=DIRECTION('',(1.,0.,0.));
#2461=AXIS2_PLACEMENT_3D('',#2458,#2459,#2460);
#2462=PLANE('',#2461);
#2463=ORIENTED_EDGE('',*,*,#2450,.T.);
#2464=EDGE_LOOP('',(#2463));
#2465=FACE_BOUND('',#2464,.T.);
#2466=ADVANCED_FACE('F1481',(#2465),#2462,.T.);
#2467=CARTESIAN_POINT('',(453.,2.99999999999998,15.));
#2468=DIRECTION('',(0.,0.,-1.));
#2469=DIRECTION('',(-1.,0.,0.));
#2470=AXIS2_PLACEMENT_3D('',#2467,#2468,#2469);
#2471=CYLINDRICAL_SURFACE('',#2470,3.);
#2472=ORIENTED_EDGE('',*,*,#188,.F.);
#2473=ORIENTED_EDGE('',*,*,#1393,.F.);
#2474=ORIENTED_EDGE('',*,*,#826,.F.);
#2475=ORIENTED_EDGE('',*,*,#1415,.F.);
#2476=EDGE_LOOP('',(#2472,#2473,#2474,#2475));
#2477=FACE_BOUND('',#2476,.T.);
#2478=ADVANCED_FACE('F918',(#2477),#2471,.T.);
#2479=CARTESIAN_POINT('',(447.,6.99999999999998,15.));
#2480=DIRECTION('',(0.,0.,1.));
#2481=DIRECTION('',(1.,0.,0.));
#2482=AXIS2_PLACEMENT_3D('',#2479,#2480,#2481);
#2483=CYLINDRICAL_SURFACE('',#2482,3.);
#2484=ORIENTED_EDGE('',*,*,#269,.F.);
#2485=ORIENTED_EDGE('',*,*,#1371,.F.);
#2486=ORIENTED_EDGE('',*,*,#843,.F.);
#2487=ORIENTED_EDGE('',*,*,#1400,.F.);
#2488=EDGE_LOOP('',(#2484,#2485,#2486,#2487));
#2489=FACE_BOUND('',#2488,.T.);
#2490=ADVANCED_FACE('F909',(#2489),#2483,.F.);
#2491=CARTESIAN_POINT('',(153.,6.99999999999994,15.));
#2492=DIRECTION('',(0.,0.,1.));
#2493=DIRECTION('',(1.,0.,0.));
#2494=AXIS2_PLACEMENT_3D('',#2491,#2492,#2493);
#2495=CYLINDRICAL_SURFACE('',#2494,3.);
#2496=ORIENTED_EDGE('',*,*,#254,.F.);
#2497=ORIENTED_EDGE('',*,*,#1349,.F.);
#2498=ORIENTED_EDGE('',*,*,#860,.F.);
#2499=ORIENTED_EDGE('',*,*,#1378,.F.);
#2500=EDGE_LOOP('',(#2496,#2497,#2498,#2499));
#2501=FACE_BOUND('',#2500,.T.);
#2502=ADVANCED_FACE('F902',(#2501),#2495,.F.);
#2503=CARTESIAN_POINT('',(147.,3.00000000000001,15.));
#2504=DIRECTION('',(0.,0.,-1.));
#2505=DIRECTION('',(-1.,0.,0.));
#2506=AXIS2_PLACEMENT_3D('',#2503,#2504,#2505);
#2507=CYLINDRICAL_SURFACE('',#2506,3.);
#2508=ORIENTED_EDGE('',*,*,#237,.F.);
#2509=ORIENTED_EDGE('',*,*,#1327,.F.);
#2510=ORIENTED_EDGE('',*,*,#877,.F.);
#2511=ORIENTED_EDGE('',*,*,#1356,.F.);
#2512=EDGE_LOOP('',(#2508,#2509,#2510,#2511));
#2513=FACE_BOUND('',#2512,.T.);
#2514=ADVANCED_FACE('F37',(#2513),#2507,.T.);
#2515=CLOSED_SHELL('',(#678,#1316,#1338,#1360,#1382,#1404,#1426,#1443,#1460,#1472,#1494,#1511,
#1528,#1545,#1562,#1579,#1596,#1608,#1630,#1647,#1664,#1681,#1698,#1715,#1732,#1744,#1766,#1783,
#1800,#1817,#1834,#1851,#1868,#1880,#1902,#1919,#1936,#1953,#1970,#1987,#2004,#2016,#2028,#2040,
#2052,#2064,#2076,#2098,#2115,#2132,#2149,#2166,#2183,#2200,#2212,#2234,#2251,#2268,#2285,#2302,
#2319,#2336,#2348,#2360,#2372,#2384,#2396,#2408,#2428,#2437,#2457,#2466,#2478,#2490,#2502,#2514));
#2516=MANIFOLD_SOLID_BREP('B2',#2515);
#2517=ADVANCED_BREP_SHAPE_REPRESENTATION('',(#18,#2516),#14);
#2518=SHAPE_DEFINITION_REPRESENTATION(#9,#2517);
ENDSEC;
END-ISO-10303-21;
